# LEF file generated by Abstract Generator version 5.5.10 on Jul 28 14:08:17 2004
#
# Contains LEF for all bins.
# Options:   [x] Antenna
#            [x] Geometry
#            [x] Technology

VERSION 5.4 ;
NAMESCASESENSITIVE ON ;
BUSBITCHARS "[]" ;
DIVIDERCHAR "/" ;
UNITS
  DATABASE MICRONS 1000 ;
END UNITS

USEMINSPACING OBS ON ;
USEMINSPACING PIN OFF ;
CLEARANCEMEASURE EUCLIDEAN ;


MANUFACTURINGGRID 0.075 ;

LAYER nwell
  TYPE	MASTERSLICE ;
END nwell

LAYER nactive
  TYPE	MASTERSLICE ;
END nactive

LAYER pactive
  TYPE	MASTERSLICE ;
END pactive

LAYER poly
  TYPE	MASTERSLICE ;
END poly

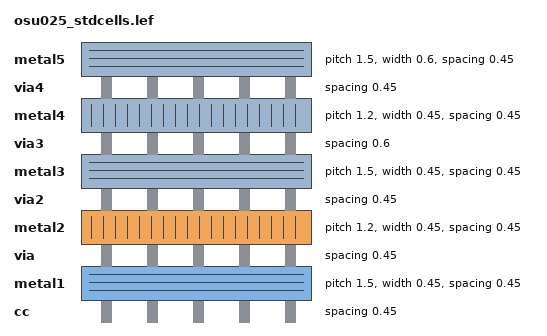
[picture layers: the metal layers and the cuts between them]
LAYER cc
  TYPE	CUT ;
  SPACING	0.45 ;
END cc

LAYER metal1
  TYPE		ROUTING ;
  DIRECTION	HORIZONTAL ;
  PITCH		1.5  ;
  WIDTH		0.45 ;
  SPACING	0.45 ;
  RESISTANCE	RPERSQ 0.07 ;
  CAPACITANCE	CPERSQDIST 3.6e-05 ;
END metal1

LAYER via
  TYPE	CUT ;
  SPACING	0.45 ;
END via

LAYER metal2
  TYPE		ROUTING ;
  DIRECTION	VERTICAL ;
  PITCH		1.2  ;
  WIDTH		0.45 ;
  SPACING	0.45 ;
  RESISTANCE	RPERSQ 0.07 ;
  CAPACITANCE	CPERSQDIST 1.6e-05 ;
END metal2

LAYER via2
  TYPE	CUT ;
  SPACING	0.45 ;
END via2

LAYER metal3
  TYPE		ROUTING ;
  DIRECTION	HORIZONTAL ;
  PITCH		1.5  ;
  WIDTH		0.45 ;
  SPACING	0.45 ;
  RESISTANCE	RPERSQ 0.07 ;
  CAPACITANCE	CPERSQDIST 1e-05 ;
END metal3

LAYER via3
  TYPE	CUT ;
  SPACING	0.6 ;
END via3

LAYER metal4
  TYPE		ROUTING ;
  DIRECTION	VERTICAL ;
  PITCH		1.2  ;
  WIDTH		0.45 ;
  SPACING	0.45 ;
  RESISTANCE	RPERSQ 0.07 ;
  CAPACITANCE	CPERSQDIST 5e-06 ;
END metal4

LAYER via4
  TYPE	CUT ;
  SPACING	0.45 ;
END via4

LAYER metal5
  TYPE		ROUTING ;
  DIRECTION	HORIZONTAL ;
  PITCH		1.5  ;
  WIDTH		0.6 ;
  SPACING	0.45 ;
  RESISTANCE	RPERSQ 0.02 ;
  CAPACITANCE	CPERSQDIST 4e-06 ;
END metal5

VIA M2_M1 DEFAULT
  LAYER metal1 ;
    RECT -0.300 -0.300 0.300 0.300 ;
  LAYER via ;
    RECT -0.150 -0.150 0.150 0.150 ;
  LAYER metal2 ;
    RECT -0.300 -0.300 0.300 0.300 ;
END M2_M1

VIA M3_M2 DEFAULT
  LAYER metal2 ;
    RECT -0.300 -0.300 0.300 0.300 ;
  LAYER via2 ;
    RECT -0.150 -0.150 0.150 0.150 ;
  LAYER metal3 ;
    RECT -0.300 -0.300 0.300 0.300 ;
END M3_M2

VIA M4_M3 DEFAULT
  LAYER metal3 ;
    RECT -0.300 -0.300 0.300 0.300 ;
  LAYER via3 ;
    RECT -0.150 -0.150 0.150 0.150 ;
  LAYER metal4 ;
    RECT -0.300 -0.300 0.300 0.300 ;
END M4_M3

VIA M5_M4 DEFAULT
  LAYER metal4 ;
    RECT -0.300 -0.300 0.300 0.300 ;
  LAYER via4 ;
    RECT -0.150 -0.150 0.150 0.150 ;
  LAYER metal5 ;
    RECT -0.300 -0.300 0.300 0.300 ;
END M5_M4


VIARULE viagen21 GENERATE
  LAYER metal1 ;
    DIRECTION HORIZONTAL ;
    WIDTH 0.6 TO 60 ;
    OVERHANG 0.15 ;
    METALOVERHANG 0 ;
  LAYER metal2 ;
    DIRECTION VERTICAL ;
    WIDTH 0.6 TO 60 ;
    OVERHANG 0.15 ;
    METALOVERHANG 0 ;
  LAYER via ;
    RECT -0.15 -0.15 0.15 0.15 ;
    SPACING 0.75 BY 0.75 ;
END viagen21

VIARULE viagen32 GENERATE
  LAYER metal3 ;
    DIRECTION HORIZONTAL ;
    WIDTH 0.6 TO 60 ;
    OVERHANG 0.15 ;
    METALOVERHANG 0 ;
  LAYER metal2 ;
    DIRECTION VERTICAL ;
    WIDTH 0.6 TO 60 ;
    OVERHANG 0.15 ;
    METALOVERHANG 0 ;
  LAYER via2 ;
    RECT -0.15 -0.15 0.15 0.15 ;
    SPACING 0.75 BY 0.75 ;
END viagen32

VIARULE viagen43 GENERATE
  LAYER metal3 ;
    DIRECTION HORIZONTAL ;
    WIDTH 0.6 TO 60 ;
    OVERHANG 0.15 ;
    METALOVERHANG 0 ;
  LAYER metal4 ;
    DIRECTION VERTICAL ;
    WIDTH 0.6 TO 60 ;
    OVERHANG 0.15 ;
    METALOVERHANG 0 ;
  LAYER via3 ;
    RECT -0.15 -0.15 0.15 0.15 ;
    SPACING 0.9 BY 0.9 ;
END viagen43

VIARULE viagen54 GENERATE
  LAYER metal5 ;
    DIRECTION HORIZONTAL ;
    WIDTH 0.6 TO 60 ;
    OVERHANG 0.15 ;
    METALOVERHANG 0 ;
  LAYER metal4 ;
    DIRECTION VERTICAL ;
    WIDTH 0.6 TO 60 ;
    OVERHANG 0.15 ;
    METALOVERHANG 0 ;
  LAYER via4 ;
    RECT -0.15 -0.15 0.15 0.15 ;
    SPACING 0.75 BY 0.75 ;
END viagen54

VIARULE TURN1 GENERATE
  LAYER metal1 ;
    DIRECTION HORIZONTAL ;
  LAYER metal1 ;
    DIRECTION VERTICAL ;
END TURN1

VIARULE TURN2 GENERATE
  LAYER metal2 ;
    DIRECTION HORIZONTAL ;
  LAYER metal2 ;
    DIRECTION VERTICAL ;
END TURN2

VIARULE TURN3 GENERATE
  LAYER metal3 ;
    DIRECTION HORIZONTAL ;
  LAYER metal3 ;
    DIRECTION VERTICAL ;
END TURN3

VIARULE TURN4 GENERATE
  LAYER metal4 ;
    DIRECTION HORIZONTAL ;
  LAYER metal4 ;
    DIRECTION VERTICAL ;
END TURN4

VIARULE TURN5 GENERATE
  LAYER metal5 ;
    DIRECTION HORIZONTAL ;
  LAYER metal5 ;
    DIRECTION VERTICAL ;
END TURN5

SITE  core
    CLASS	CORE ;
    SYMMETRY	Y ;
    SIZE	1.200 BY 15.000 ;
END  core

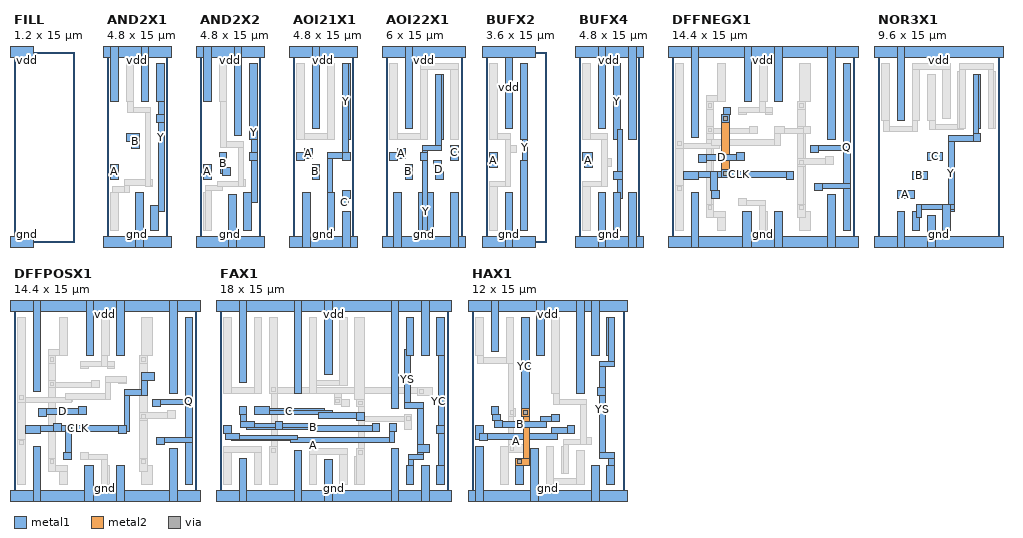
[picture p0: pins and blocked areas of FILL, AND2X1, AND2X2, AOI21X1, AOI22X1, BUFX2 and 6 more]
MACRO FILL
  CLASS  CORE ;
  FOREIGN FILL 0.000 0.000 ;
  ORIGIN 0.000 0.000 ;
  SIZE 1.200 BY 15.000 ;
  SYMMETRY X Y  ;
  SITE core ;
  PIN gnd
    DIRECTION INOUT ;
    USE GROUND ;
    SHAPE ABUTMENT ;
    PORT
      LAYER metal1 ;
        RECT -0.300 -0.450 1.500 0.450 ;
    END
  END gnd
  PIN vdd
    DIRECTION INOUT ;
    USE POWER ;
    SHAPE ABUTMENT ;
    PORT
      LAYER metal1 ;
        RECT -0.300 14.550 1.500 15.450 ;
    END
  END vdd
END FILL

MACRO AND2X1
  CLASS  CORE ;
  FOREIGN AND2X1 0.000 0.000 ;
  ORIGIN 0.000 0.000 ;
  SIZE 4.800 BY 15.000 ;
  SYMMETRY X Y  ;
  SITE core ;
  PIN A
    DIRECTION INPUT ;
    PORT
      LAYER metal1 ;
        RECT 0.300 4.950 0.900 6.150 ;
    END
  END A
  PIN B
    DIRECTION INPUT ;
    PORT
      LAYER metal1 ;
        RECT 1.950 7.350 2.550 8.550 ;
        RECT 1.500 7.950 2.550 8.550 ;
    END
  END B
  PIN gnd
    DIRECTION INOUT ;
    USE GROUND ;
    SHAPE ABUTMENT ;
    PORT
      LAYER metal1 ;
        RECT 2.250 -0.450 2.850 3.900 ;
        RECT -0.300 -0.450 5.100 0.450 ;
    END
  END gnd
  PIN Y
    DIRECTION OUTPUT ;
    PORT
      LAYER metal1 ;
        RECT 3.900 9.450 4.500 10.050 ;
        RECT 3.900 11.100 4.500 14.100 ;
        RECT 4.050 2.400 4.500 14.100 ;
        RECT 3.450 0.900 4.050 2.850 ;
    END
  END Y
  PIN vdd
    DIRECTION INOUT ;
    USE POWER ;
    SHAPE ABUTMENT ;
    PORT
      LAYER metal1 ;
        RECT 0.300 11.100 0.900 15.450 ;
        RECT -0.300 14.550 5.100 15.450 ;
        RECT 2.700 11.100 3.300 15.450 ;
    END
  END vdd
  OBS 
      LAYER metal1 ;
        RECT 0.300 0.900 0.900 3.900 ;
        RECT 0.450 3.900 1.800 4.350 ;
        RECT 1.350 3.900 1.800 4.950 ;
        RECT 3.000 4.350 3.600 4.950 ;
        RECT 1.350 4.500 3.600 4.950 ;
        RECT 3.000 4.350 3.450 10.650 ;
        RECT 1.650 10.200 3.450 10.650 ;
        RECT 1.650 10.200 2.100 14.100 ;
        RECT 1.500 11.100 2.100 14.100 ;
  END 
END AND2X1

MACRO AND2X2
  CLASS  CORE ;
  FOREIGN AND2X2 0.000 0.000 ;
  ORIGIN 0.000 0.000 ;
  SIZE 4.800 BY 15.000 ;
  SYMMETRY X Y  ;
  SITE core ;
  PIN A
    DIRECTION INPUT ;
    PORT
      LAYER metal1 ;
        RECT 0.300 4.950 0.900 6.150 ;
    END
  END A
  PIN B
    DIRECTION INPUT ;
    PORT
      LAYER metal1 ;
        RECT 1.650 5.400 2.100 7.050 ;
        RECT 1.800 5.250 2.400 5.850 ;
        RECT 1.500 6.450 2.100 7.050 ;
    END
  END B
  PIN gnd
    DIRECTION INOUT ;
    USE GROUND ;
    SHAPE ABUTMENT ;
    PORT
      LAYER metal1 ;
        RECT 2.250 -0.450 2.850 3.750 ;
        RECT -0.300 -0.450 5.100 0.450 ;
    END
  END gnd
  PIN Y
    DIRECTION OUTPUT ;
    PORT
      LAYER metal1 ;
        RECT 3.900 6.450 4.500 7.050 ;
        RECT 3.900 8.100 4.500 14.100 ;
        RECT 4.050 3.150 4.500 14.100 ;
        RECT 3.450 0.900 4.050 3.900 ;
    END
  END Y
  PIN vdd
    DIRECTION INOUT ;
    USE POWER ;
    SHAPE ABUTMENT ;
    PORT
      LAYER metal1 ;
        RECT 0.300 11.100 0.900 15.450 ;
        RECT -0.300 14.550 5.100 15.450 ;
        RECT 2.700 8.400 3.300 15.450 ;
    END
  END vdd
  OBS 
      LAYER metal1 ;
        RECT 0.300 0.900 0.900 3.900 ;
        RECT 0.450 0.900 0.900 4.500 ;
        RECT 0.450 4.050 1.800 4.500 ;
        RECT 1.350 4.350 3.600 4.800 ;
        RECT 3.000 4.350 3.600 4.950 ;
        RECT 3.000 4.350 3.450 7.950 ;
        RECT 1.650 7.500 3.450 7.950 ;
        RECT 1.650 7.500 2.100 14.100 ;
        RECT 1.500 11.100 2.100 14.100 ;
  END 
END AND2X2

MACRO AOI21X1
  CLASS  CORE ;
  FOREIGN AOI21X1 0.000 0.000 ;
  ORIGIN 0.000 0.000 ;
  SIZE 4.800 BY 15.000 ;
  SYMMETRY X Y  ;
  SITE core ;
  PIN A
    DIRECTION INPUT ;
    PORT
      LAYER metal1 ;
        RECT 0.300 6.450 0.900 7.050 ;
        RECT 0.900 6.600 1.500 7.350 ;
    END
  END A
  PIN B
    DIRECTION INPUT ;
    PORT
      LAYER metal1 ;
        RECT 1.500 4.950 2.100 6.150 ;
    END
  END B
  PIN C
    DIRECTION INPUT ;
    PORT
      LAYER metal1 ;
        RECT 3.750 2.850 4.350 3.450 ;
        RECT 3.900 3.450 4.500 4.050 ;
    END
  END C
  PIN gnd
    DIRECTION INOUT ;
    USE GROUND ;
    SHAPE ABUTMENT ;
    PORT
      LAYER metal1 ;
        RECT 0.750 -0.450 1.350 3.900 ;
        RECT -0.300 -0.450 5.100 0.450 ;
        RECT 3.900 -0.450 4.500 2.400 ;
    END
  END gnd
  PIN Y
    DIRECTION OUTPUT ;
    PORT
      LAYER metal1 ;
        RECT 2.700 0.900 3.150 7.050 ;
        RECT 3.900 8.100 4.500 14.100 ;
        RECT 2.700 6.600 4.500 7.050 ;
        RECT 3.900 6.450 4.500 7.050 ;
        RECT 3.900 6.450 4.350 14.100 ;
        RECT 2.700 0.900 3.300 3.900 ;
    END
  END Y
  PIN vdd
    DIRECTION INOUT ;
    USE POWER ;
    SHAPE ABUTMENT ;
    PORT
      LAYER metal1 ;
        RECT 1.500 9.000 2.100 15.450 ;
        RECT -0.300 14.550 5.100 15.450 ;
    END
  END vdd
  OBS 
      LAYER metal1 ;
        RECT 0.300 8.100 3.300 8.550 ;
        RECT 0.300 8.100 0.900 14.100 ;
        RECT 2.700 8.100 3.300 14.100 ;
  END 
END AOI21X1

MACRO AOI22X1
  CLASS  CORE ;
  FOREIGN AOI22X1 0.000 0.000 ;
  ORIGIN 0.000 0.000 ;
  SIZE 6.000 BY 15.000 ;
  SYMMETRY X Y  ;
  SITE core ;
  PIN A
    DIRECTION INPUT ;
    PORT
      LAYER metal1 ;
        RECT 0.300 6.450 0.900 7.050 ;
        RECT 0.900 6.600 1.500 7.350 ;
    END
  END A
  PIN B
    DIRECTION INPUT ;
    PORT
      LAYER metal1 ;
        RECT 1.500 4.950 2.100 6.150 ;
    END
  END B
  PIN C
    DIRECTION INPUT ;
    PORT
      LAYER metal1 ;
        RECT 5.100 6.450 5.700 7.650 ;
    END
  END C
  PIN D
    DIRECTION INPUT ;
    PORT
      LAYER metal1 ;
        RECT 3.900 4.950 4.350 6.450 ;
        RECT 3.900 4.950 4.500 5.550 ;
        RECT 3.750 5.850 4.350 6.450 ;
    END
  END D
  PIN gnd
    DIRECTION INOUT ;
    USE GROUND ;
    SHAPE ABUTMENT ;
    PORT
      LAYER metal1 ;
        RECT 0.600 -0.450 1.200 3.900 ;
        RECT -0.300 -0.450 6.300 0.450 ;
        RECT 5.100 -0.450 5.700 3.900 ;
    END
  END gnd
  PIN Y
    DIRECTION OUTPUT ;
    PORT
      LAYER metal1 ;
        RECT 2.700 6.450 3.300 7.050 ;
        RECT 3.900 8.100 4.500 13.200 ;
        RECT 3.900 7.200 4.350 13.200 ;
        RECT 2.850 7.200 4.350 7.650 ;
        RECT 2.550 0.900 3.750 3.900 ;
        RECT 2.850 0.900 3.300 7.650 ;
    END
  END Y
  PIN vdd
    DIRECTION INOUT ;
    USE POWER ;
    SHAPE ABUTMENT ;
    PORT
      LAYER metal1 ;
        RECT 1.500 9.000 2.100 15.450 ;
        RECT -0.300 14.550 6.300 15.450 ;
    END
  END vdd
  OBS 
      LAYER metal1 ;
        RECT 0.300 8.100 3.300 8.550 ;
        RECT 2.700 8.100 3.300 14.100 ;
        RECT 0.300 8.100 0.900 14.100 ;
        RECT 5.100 8.100 5.700 14.100 ;
        RECT 2.700 13.650 5.700 14.100 ;
  END 
END AOI22X1

MACRO BUFX2
  CLASS  CORE ;
  FOREIGN BUFX2 0.000 0.000 ;
  ORIGIN 0.000 0.000 ;
  SIZE 3.600 BY 15.000 ;
  SYMMETRY X Y  ;
  SITE core ;
  PIN A
    DIRECTION INPUT ;
    PORT
      LAYER metal1 ;
        RECT 0.300 5.850 0.900 7.050 ;
    END
  END A
  PIN gnd
    DIRECTION INOUT ;
    USE GROUND ;
    SHAPE ABUTMENT ;
    PORT
      LAYER metal1 ;
        RECT 1.500 -0.450 2.100 3.900 ;
        RECT -0.300 -0.450 3.900 0.450 ;
    END
  END gnd
  PIN Y
    DIRECTION OUTPUT ;
    PORT
      LAYER metal1 ;
        RECT 2.700 0.900 3.300 6.450 ;
        RECT 2.700 8.100 3.300 14.100 ;
        RECT 2.850 0.900 3.300 14.100 ;
    END
  END Y
  PIN vdd
    DIRECTION INOUT ;
    USE POWER ;
    SHAPE ABUTMENT ;
    PORT
      LAYER metal1 ;
        RECT 1.500 9.000 2.100 15.450 ;
        RECT -0.300 14.550 3.900 15.450 ;
    END
  END vdd
  OBS 
      LAYER metal1 ;
        RECT 0.300 0.900 0.900 4.800 ;
        RECT 0.300 4.350 1.950 4.800 ;
        RECT 1.500 7.050 2.400 7.650 ;
        RECT 1.500 4.350 1.950 8.550 ;
        RECT 0.300 8.100 1.950 8.550 ;
        RECT 0.300 8.100 0.900 14.100 ;
  END 
END BUFX2

MACRO BUFX4
  CLASS  CORE ;
  FOREIGN BUFX4 0.000 0.000 ;
  ORIGIN 0.000 0.000 ;
  SIZE 4.800 BY 15.000 ;
  SYMMETRY X Y  ;
  SITE core ;
  PIN A
    DIRECTION INPUT ;
    PORT
      LAYER metal1 ;
        RECT 0.450 5.850 1.050 7.050 ;
        RECT 0.300 6.450 1.050 7.050 ;
    END
  END A
  PIN gnd
    DIRECTION INOUT ;
    USE GROUND ;
    SHAPE ABUTMENT ;
    PORT
      LAYER metal1 ;
        RECT 1.500 -0.450 2.100 3.900 ;
        RECT -0.300 -0.450 5.100 0.450 ;
        RECT 3.900 -0.450 4.500 3.900 ;
    END
  END gnd
  PIN Y
    DIRECTION OUTPUT ;
    PORT
      LAYER metal1 ;
        RECT 2.700 0.900 3.300 3.900 ;
        RECT 3.000 3.450 3.450 8.850 ;
        RECT 2.700 8.100 3.300 14.100 ;
        RECT 2.700 4.950 3.450 5.550 ;
    END
  END Y
  PIN vdd
    DIRECTION INOUT ;
    USE POWER ;
    SHAPE ABUTMENT ;
    PORT
      LAYER metal1 ;
        RECT 1.500 9.000 2.100 15.450 ;
        RECT -0.300 14.550 5.100 15.450 ;
        RECT 3.900 8.100 4.500 15.450 ;
    END
  END vdd
  OBS 
      LAYER metal1 ;
        RECT 0.300 0.900 0.900 4.800 ;
        RECT 0.300 4.350 2.250 4.800 ;
        RECT 1.800 6.000 2.550 6.600 ;
        RECT 1.800 4.350 2.250 8.550 ;
        RECT 0.300 8.100 2.250 8.550 ;
        RECT 0.300 8.100 0.900 14.100 ;
  END 
END BUFX4

MACRO DFFNEGX1
  CLASS  CORE ;
  FOREIGN DFFNEGX1 0.000 0.000 ;
  ORIGIN 0.000 0.000 ;
  SIZE 14.400 BY 15.000 ;
  SYMMETRY X Y  ;
  SITE core ;
  PIN Q
    DIRECTION OUTPUT ;
    PORT
      LAYER metal1 ;
        RECT 10.950 7.050 11.550 7.650 ;
        RECT 13.500 0.900 14.100 14.100 ;
        RECT 10.950 7.200 14.100 7.650 ;
        RECT 11.250 4.200 14.100 4.650 ;
        RECT 11.250 4.050 11.850 4.650 ;
    END
  END Q
  PIN CLK
    DIRECTION INPUT ;
    USE CLOCK ;
    PORT
      LAYER metal2 ;
        RECT 3.900 5.100 4.500 10.050 ;
      LAYER via ;
        RECT 4.050 9.600 4.350 9.900 ;
        RECT 4.050 5.250 4.350 5.550 ;
      LAYER metal1 ;
        RECT 3.900 9.450 4.500 10.050 ;
        RECT 0.900 5.100 9.600 5.550 ;
        RECT 9.000 4.950 9.600 5.550 ;
        RECT 3.900 5.100 4.500 5.700 ;
        RECT 3.150 3.450 3.750 4.050 ;
        RECT 3.000 4.050 3.600 5.550 ;
        RECT 0.900 4.950 2.100 5.550 ;
        RECT 4.050 10.050 4.650 10.650 ;
    END
  END CLK
  PIN D
    DIRECTION INPUT ;
    PORT
      LAYER metal1 ;
        RECT 2.100 6.300 2.700 6.900 ;
        RECT 5.100 6.450 5.700 7.050 ;
        RECT 2.100 6.450 5.700 6.900 ;
    END
  END D
  PIN gnd
    DIRECTION INOUT ;
    USE GROUND ;
    SHAPE ABUTMENT ;
    PORT
      LAYER metal1 ;
        RECT 1.500 -0.450 2.100 3.900 ;
        RECT -0.300 -0.450 14.700 0.450 ;
        RECT 12.300 -0.450 12.900 3.750 ;
        RECT 8.100 -0.450 8.700 2.400 ;
        RECT 5.550 -0.450 6.300 2.400 ;
    END
  END gnd
  PIN vdd
    DIRECTION INOUT ;
    USE POWER ;
    SHAPE ABUTMENT ;
    PORT
      LAYER metal1 ;
        RECT 1.500 8.250 2.100 15.450 ;
        RECT -0.300 14.550 14.700 15.450 ;
        RECT 12.300 8.100 12.900 15.450 ;
        RECT 8.100 11.100 8.700 15.450 ;
        RECT 5.700 11.100 6.300 15.450 ;
    END
  END vdd
  OBS 
      LAYER metal2 ;
        RECT 0.300 3.900 0.900 8.100 ;
        RECT 2.700 2.400 3.300 7.500 ;
        RECT 2.700 2.400 3.150 11.100 ;
        RECT 2.700 8.100 3.300 11.100 ;
        RECT 9.900 2.400 10.500 8.550 ;
        RECT 9.900 2.400 10.350 11.100 ;
        RECT 9.900 9.150 10.500 11.100 ;
      LAYER metal1 ;
        RECT 0.300 0.900 0.900 4.500 ;
        RECT 2.700 10.500 3.300 11.550 ;
        RECT 2.700 11.100 4.200 11.550 ;
        RECT 3.600 11.100 4.200 14.100 ;
        RECT 3.600 0.900 4.200 2.400 ;
        RECT 2.700 1.950 4.200 2.400 ;
        RECT 2.700 1.950 3.300 3.000 ;
        RECT 2.700 8.550 6.750 9.000 ;
        RECT 2.700 8.550 3.300 9.150 ;
        RECT 6.150 8.550 6.750 9.150 ;
        RECT 6.900 0.900 7.500 2.400 ;
        RECT 6.900 0.900 7.350 3.300 ;
        RECT 5.250 2.850 7.350 3.300 ;
        RECT 5.250 2.850 5.850 3.450 ;
        RECT 5.250 10.050 5.850 10.650 ;
        RECT 7.350 10.050 7.950 10.650 ;
        RECT 5.250 10.200 7.950 10.650 ;
        RECT 6.900 10.200 7.350 14.100 ;
        RECT 6.900 11.100 7.500 14.100 ;
        RECT 9.900 10.500 10.500 11.100 ;
        RECT 10.050 11.100 10.950 14.100 ;
        RECT 0.300 7.350 3.750 7.800 ;
        RECT 3.150 7.650 8.550 8.100 ;
        RECT 8.100 7.650 8.550 9.150 ;
        RECT 8.100 8.550 10.950 9.000 ;
        RECT 8.100 8.550 8.850 9.150 ;
        RECT 10.350 8.550 10.950 9.150 ;
        RECT 0.300 7.350 0.900 14.100 ;
        RECT 10.050 0.900 10.950 2.400 ;
        RECT 9.900 1.950 10.500 3.000 ;
        RECT 9.900 6.000 10.500 6.600 ;
        RECT 9.900 6.150 12.750 6.600 ;
        RECT 12.150 6.150 12.750 6.750 ;
      LAYER via ;
        RECT 0.450 7.650 0.750 7.950 ;
        RECT 0.450 4.050 0.750 4.350 ;
        RECT 2.850 10.650 3.150 10.950 ;
        RECT 2.850 8.700 3.150 9.000 ;
        RECT 2.850 2.550 3.150 2.850 ;
        RECT 10.050 10.650 10.350 10.950 ;
        RECT 10.050 6.150 10.350 6.450 ;
        RECT 10.050 2.550 10.350 2.850 ;
  END 
END DFFNEGX1

MACRO NOR3X1
  CLASS  CORE ;
  FOREIGN NOR3X1 0.000 0.000 ;
  ORIGIN 0.000 0.000 ;
  SIZE 9.600 BY 15.000 ;
  SYMMETRY X Y  ;
  SITE core ;
  PIN A
    DIRECTION INPUT ;
    PORT
      LAYER metal1 ;
        RECT 1.500 3.450 2.850 4.050 ;
    END
  END A
  PIN B
    DIRECTION INPUT ;
    PORT
      LAYER metal1 ;
        RECT 2.700 4.950 3.900 5.550 ;
    END
  END B
  PIN C
    DIRECTION INPUT ;
    PORT
      LAYER metal1 ;
        RECT 3.900 6.450 5.100 7.050 ;
    END
  END C
  PIN gnd
    DIRECTION INOUT ;
    USE GROUND ;
    SHAPE ABUTMENT ;
    PORT
      LAYER metal1 ;
        RECT 1.500 -0.450 2.100 2.400 ;
        RECT -0.300 -0.450 9.900 0.450 ;
        RECT 3.900 -0.450 4.500 2.100 ;
    END
  END gnd
  PIN Y
    DIRECTION OUTPUT ;
    PORT
      LAYER metal1 ;
        RECT 2.700 0.900 3.300 2.400 ;
        RECT 7.500 9.000 8.100 13.200 ;
        RECT 7.500 7.950 8.100 8.550 ;
        RECT 7.500 7.950 7.950 13.200 ;
        RECT 5.550 7.950 8.100 8.400 ;
        RECT 5.550 2.400 6.000 8.400 ;
        RECT 5.100 0.900 5.700 3.000 ;
        RECT 3.000 2.550 6.000 3.000 ;
        RECT 3.000 1.950 3.450 3.000 ;
    END
  END Y
  PIN vdd
    DIRECTION INOUT ;
    USE POWER ;
    SHAPE ABUTMENT ;
    PORT
      LAYER metal1 ;
        RECT 1.500 9.600 2.100 15.450 ;
        RECT -0.300 14.550 9.900 15.450 ;
    END
  END vdd
  OBS 
      LAYER metal1 ;
        RECT 0.450 8.700 3.150 9.150 ;
        RECT 2.700 8.700 3.150 14.100 ;
        RECT 2.700 9.600 3.300 14.100 ;
        RECT 0.450 8.700 0.900 14.100 ;
        RECT 0.300 9.600 0.900 14.100 ;
        RECT 5.100 9.750 5.700 14.100 ;
        RECT 2.700 13.650 5.700 14.100 ;
        RECT 4.050 8.850 6.750 9.300 ;
        RECT 4.050 8.850 4.500 13.200 ;
        RECT 3.900 9.600 4.500 13.200 ;
        RECT 6.300 9.000 6.900 13.500 ;
        RECT 8.700 9.000 9.300 13.500 ;
        RECT 6.450 9.000 6.900 14.100 ;
        RECT 8.700 9.000 9.150 14.100 ;
        RECT 6.450 13.650 9.150 14.100 ;
  END 
END NOR3X1

MACRO DFFPOSX1
  CLASS  CORE ;
  FOREIGN DFFPOSX1 0.000 0.000 ;
  ORIGIN 0.000 0.000 ;
  SIZE 14.400 BY 15.000 ;
  SYMMETRY X Y  ;
  SITE core ;
  PIN Q
    DIRECTION OUTPUT ;
    PORT
      LAYER metal1 ;
        RECT 10.950 7.050 11.550 7.650 ;
        RECT 13.500 0.900 14.100 14.100 ;
        RECT 10.950 7.200 14.100 7.650 ;
        RECT 11.250 4.200 14.100 4.650 ;
        RECT 11.250 4.050 11.850 4.650 ;
    END
  END Q
  PIN CLK
    DIRECTION INPUT ;
    USE CLOCK ;
    PORT
      LAYER metal1 ;
        RECT 0.900 4.950 2.100 5.550 ;
        RECT 10.050 9.150 11.100 9.750 ;
        RECT 10.050 7.950 10.500 9.750 ;
        RECT 8.700 7.950 10.500 8.400 ;
        RECT 8.700 5.100 9.150 8.400 ;
        RECT 8.250 4.950 8.850 5.550 ;
        RECT 0.900 5.100 9.150 5.550 ;
        RECT 4.050 2.850 4.500 5.550 ;
        RECT 3.900 2.850 4.500 3.450 ;
        RECT 3.150 5.100 3.750 5.700 ;
    END
  END CLK
  PIN D
    DIRECTION INPUT ;
    PORT
      LAYER metal1 ;
        RECT 1.950 6.300 2.550 6.900 ;
        RECT 5.100 6.450 5.700 7.050 ;
        RECT 1.950 6.450 5.700 6.900 ;
    END
  END D
  PIN gnd
    DIRECTION INOUT ;
    USE GROUND ;
    SHAPE ABUTMENT ;
    PORT
      LAYER metal1 ;
        RECT 1.500 -0.450 2.100 3.900 ;
        RECT -0.300 -0.450 14.700 0.450 ;
        RECT 12.300 -0.450 12.900 3.750 ;
        RECT 8.100 -0.450 8.700 2.400 ;
        RECT 5.550 -0.450 6.300 2.400 ;
    END
  END gnd
  PIN vdd
    DIRECTION INOUT ;
    USE POWER ;
    SHAPE ABUTMENT ;
    PORT
      LAYER metal1 ;
        RECT 1.500 8.250 2.100 15.450 ;
        RECT -0.300 14.550 14.700 15.450 ;
        RECT 12.300 8.100 12.900 15.450 ;
        RECT 8.100 11.100 8.700 15.450 ;
        RECT 5.700 11.100 6.300 15.450 ;
    END
  END vdd
  OBS 
      LAYER metal2 ;
        RECT 0.300 3.900 0.900 8.100 ;
        RECT 2.700 2.400 3.300 11.100 ;
        RECT 9.900 2.400 10.500 11.100 ;
      LAYER metal1 ;
        RECT 0.300 0.900 0.900 4.500 ;
        RECT 2.700 10.500 3.300 11.550 ;
        RECT 2.700 11.100 4.200 11.550 ;
        RECT 3.600 11.100 4.200 14.100 ;
        RECT 3.600 0.900 4.200 2.400 ;
        RECT 2.700 1.950 4.200 2.400 ;
        RECT 2.700 1.950 3.300 3.000 ;
        RECT 2.700 8.550 6.750 9.000 ;
        RECT 2.700 8.550 3.300 9.150 ;
        RECT 6.150 8.550 6.750 9.150 ;
        RECT 6.900 0.900 7.500 2.400 ;
        RECT 6.900 0.900 7.350 3.300 ;
        RECT 5.250 2.850 7.350 3.300 ;
        RECT 5.250 2.850 5.850 3.450 ;
        RECT 5.250 10.050 5.850 10.650 ;
        RECT 7.350 10.050 7.950 10.650 ;
        RECT 5.250 10.200 7.950 10.650 ;
        RECT 6.900 10.200 7.350 14.100 ;
        RECT 6.900 11.100 7.500 14.100 ;
        RECT 0.300 7.500 4.650 7.800 ;
        RECT 0.300 7.350 4.500 7.800 ;
        RECT 4.050 7.650 7.650 8.100 ;
        RECT 7.200 7.650 7.650 9.450 ;
        RECT 8.250 8.850 8.850 9.450 ;
        RECT 7.200 9.000 8.850 9.450 ;
        RECT 0.300 7.350 0.900 14.100 ;
        RECT 9.900 10.500 10.500 11.100 ;
        RECT 10.050 11.100 10.950 14.100 ;
        RECT 10.050 0.900 10.950 2.400 ;
        RECT 9.900 1.950 10.500 3.000 ;
        RECT 9.900 6.000 10.500 6.600 ;
        RECT 9.900 6.150 12.750 6.600 ;
        RECT 12.150 6.150 12.750 6.750 ;
      LAYER via ;
        RECT 0.450 7.650 0.750 7.950 ;
        RECT 0.450 4.050 0.750 4.350 ;
        RECT 2.850 10.650 3.150 10.950 ;
        RECT 2.850 8.700 3.150 9.000 ;
        RECT 2.850 2.550 3.150 2.850 ;
        RECT 10.050 10.650 10.350 10.950 ;
        RECT 10.050 6.150 10.350 6.450 ;
        RECT 10.050 2.550 10.350 2.850 ;
  END 
END DFFPOSX1

MACRO FAX1
  CLASS  CORE ;
  FOREIGN FAX1 0.000 0.000 ;
  ORIGIN 0.000 0.000 ;
  SIZE 18.000 BY 15.000 ;
  SYMMETRY X Y  ;
  SITE core ;
  PIN YC
    DIRECTION OUTPUT ;
    PORT
      LAYER metal1 ;
        RECT 17.100 0.900 17.700 2.400 ;
        RECT 17.100 11.100 17.700 14.100 ;
        RECT 17.250 0.900 17.700 14.100 ;
        RECT 17.100 4.950 17.700 5.550 ;
    END
  END YC
  PIN YS
    DIRECTION OUTPUT ;
    PORT
      LAYER metal1 ;
        RECT 14.700 0.900 15.300 2.400 ;
        RECT 15.600 3.450 16.500 4.050 ;
        RECT 14.550 6.900 16.050 7.350 ;
        RECT 15.600 2.850 16.050 7.350 ;
        RECT 14.850 2.850 16.050 3.300 ;
        RECT 14.700 11.100 15.300 14.100 ;
        RECT 14.850 0.900 15.300 3.300 ;
        RECT 14.550 6.900 15.000 11.550 ;
    END
  END YS
  PIN A
    DIRECTION INPUT ;
    PORT
      LAYER metal1 ;
        RECT 0.450 4.500 1.500 4.950 ;
        RECT 13.350 5.100 13.950 5.700 ;
        RECT 13.350 4.200 13.800 5.700 ;
        RECT 5.550 4.200 13.800 4.650 ;
        RECT 0.450 4.500 6.150 4.800 ;
        RECT 0.900 4.350 13.800 4.650 ;
        RECT 0.300 4.950 0.900 5.550 ;
    END
  END A
  PIN B
    DIRECTION INPUT ;
    PORT
      LAYER metal1 ;
        RECT 1.650 5.400 2.100 7.050 ;
        RECT 12.000 5.100 12.600 5.700 ;
        RECT 7.050 5.100 12.600 5.550 ;
        RECT 1.650 5.400 7.650 5.700 ;
        RECT 2.100 5.250 12.600 5.550 ;
        RECT 4.350 5.250 4.950 5.850 ;
        RECT 1.650 5.400 2.700 5.850 ;
        RECT 1.500 6.450 2.100 7.050 ;
    END
  END B
  PIN C
    DIRECTION INPUT ;
    PORT
      LAYER metal1 ;
        RECT 2.700 6.450 3.900 7.050 ;
        RECT 10.800 6.000 11.400 6.600 ;
        RECT 7.800 6.150 11.400 6.600 ;
        RECT 2.700 6.450 8.850 6.750 ;
        RECT 2.700 6.450 8.250 6.900 ;
    END
  END C
  PIN gnd
    DIRECTION INOUT ;
    USE GROUND ;
    SHAPE ABUTMENT ;
    PORT
      LAYER metal1 ;
        RECT 1.500 -0.450 2.100 3.000 ;
        RECT -0.300 -0.450 18.300 0.450 ;
        RECT 15.900 -0.450 16.500 2.400 ;
        RECT 13.500 -0.450 14.100 3.750 ;
        RECT 8.250 -0.450 8.850 2.850 ;
        RECT 5.850 -0.450 6.450 3.600 ;
    END
  END gnd
  PIN vdd
    DIRECTION INOUT ;
    USE POWER ;
    SHAPE ABUTMENT ;
    PORT
      LAYER metal1 ;
        RECT 1.500 9.000 2.100 15.450 ;
        RECT -0.300 14.550 18.300 15.450 ;
        RECT 15.900 11.100 16.500 15.450 ;
        RECT 13.500 6.900 14.100 15.450 ;
        RECT 8.250 9.600 8.850 15.450 ;
        RECT 5.850 8.100 6.450 15.450 ;
    END
  END vdd
  OBS 
      LAYER metal2 ;
        RECT 10.800 3.150 11.400 3.750 ;
        RECT 10.950 5.850 15.150 6.300 ;
        RECT 14.550 5.850 15.150 6.450 ;
        RECT 10.950 3.150 11.400 7.650 ;
        RECT 10.800 7.050 11.400 7.650 ;
        RECT 3.900 3.300 4.500 3.900 ;
        RECT 9.000 7.200 9.600 8.550 ;
        RECT 15.600 7.950 16.200 8.550 ;
        RECT 3.900 8.100 16.200 8.550 ;
        RECT 4.050 3.300 4.500 8.700 ;
        RECT 3.900 8.100 4.500 8.700 ;
      LAYER metal1 ;
        RECT 0.300 8.100 3.300 8.550 ;
        RECT 0.300 8.100 0.900 14.100 ;
        RECT 2.700 8.100 3.300 14.100 ;
        RECT 0.300 0.900 0.900 3.900 ;
        RECT 2.700 0.900 3.300 3.900 ;
        RECT 0.300 3.450 3.300 3.900 ;
        RECT 3.900 8.100 4.500 14.100 ;
        RECT 3.900 0.900 4.500 3.900 ;
        RECT 7.050 8.700 10.050 9.150 ;
        RECT 7.050 8.100 7.650 14.100 ;
        RECT 9.450 8.700 10.050 14.100 ;
        RECT 7.050 0.900 7.650 3.750 ;
        RECT 9.450 0.900 10.050 3.750 ;
        RECT 7.050 3.300 10.050 3.750 ;
        RECT 9.600 7.050 10.200 7.650 ;
        RECT 9.000 7.200 9.600 7.800 ;
        RECT 10.800 7.050 11.400 14.100 ;
        RECT 10.650 7.650 11.400 14.100 ;
        RECT 10.650 0.900 11.400 3.150 ;
        RECT 10.800 0.900 11.400 3.750 ;
        RECT 14.550 5.250 15.150 6.450 ;
        RECT 15.600 7.950 16.800 8.550 ;
      LAYER via ;
        RECT 4.050 8.250 4.350 8.550 ;
        RECT 4.050 3.450 4.350 3.750 ;
        RECT 9.150 7.350 9.450 7.650 ;
        RECT 10.950 7.200 11.250 7.500 ;
        RECT 10.950 3.300 11.250 3.600 ;
        RECT 14.700 6.000 15.000 6.300 ;
        RECT 15.750 8.100 16.050 8.400 ;
  END 
END FAX1

MACRO HAX1
  CLASS  CORE ;
  FOREIGN HAX1 0.000 0.000 ;
  ORIGIN 0.000 0.000 ;
  SIZE 12.000 BY 15.000 ;
  SYMMETRY X Y  ;
  SITE core ;
  PIN YC
    DIRECTION OUTPUT ;
    PORT
      LAYER metal2 ;
        RECT 3.450 2.400 4.500 3.000 ;
        RECT 3.900 6.300 4.500 6.900 ;
        RECT 4.050 2.400 4.500 6.900 ;
      LAYER via ;
        RECT 3.600 2.550 3.900 2.850 ;
        RECT 4.050 6.450 4.350 6.750 ;
      LAYER metal1 ;
        RECT 3.450 0.900 4.050 3.000 ;
        RECT 3.900 6.300 4.500 14.100 ;
    END
  END YC
  PIN YS
    DIRECTION OUTPUT ;
    PORT
      LAYER metal1 ;
        RECT 9.900 7.950 10.500 8.550 ;
        RECT 10.650 11.100 11.250 14.100 ;
        RECT 10.800 10.200 11.250 14.100 ;
        RECT 10.050 3.000 11.250 3.450 ;
        RECT 10.800 0.900 11.250 3.450 ;
        RECT 10.050 10.200 11.250 10.650 ;
        RECT 10.650 0.900 11.250 2.400 ;
        RECT 10.050 3.000 10.500 10.650 ;
    END
  END YS
  PIN A
    DIRECTION INPUT ;
    PORT
      LAYER metal1 ;
        RECT 0.300 4.500 0.900 5.550 ;
        RECT 7.500 4.950 8.100 5.550 ;
        RECT 6.300 4.950 8.100 5.400 ;
        RECT 0.300 4.500 6.750 4.950 ;
        RECT 0.600 4.350 1.200 4.950 ;
    END
  END A
  PIN B
    DIRECTION INPUT ;
    PORT
      LAYER metal1 ;
        RECT 1.650 6.000 2.250 6.450 ;
        RECT 6.300 5.850 6.900 6.450 ;
        RECT 5.400 5.850 6.900 6.300 ;
        RECT 1.800 5.400 5.850 5.850 ;
        RECT 1.800 5.400 2.400 6.000 ;
        RECT 1.500 6.450 2.100 7.050 ;
    END
  END B
  PIN gnd
    DIRECTION INOUT ;
    USE GROUND ;
    SHAPE ABUTMENT ;
    PORT
      LAYER metal1 ;
        RECT 0.300 -0.450 0.900 3.900 ;
        RECT -0.300 -0.450 12.300 0.450 ;
        RECT 9.450 -0.450 10.050 2.400 ;
        RECT 4.650 -0.450 5.250 3.750 ;
    END
  END gnd
  PIN vdd
    DIRECTION INOUT ;
    USE POWER ;
    SHAPE ABUTMENT ;
    PORT
      LAYER metal1 ;
        RECT 1.500 11.400 2.100 15.450 ;
        RECT -0.300 14.550 12.300 15.450 ;
        RECT 9.450 11.100 10.050 15.450 ;
        RECT 8.250 8.100 8.850 15.450 ;
        RECT 5.100 11.100 5.700 15.450 ;
    END
  END vdd
  OBS 
      LAYER metal2 ;
        RECT 2.850 3.450 3.450 4.050 ;
        RECT 2.850 3.450 3.300 6.900 ;
        RECT 2.850 6.300 3.450 6.900 ;
      LAYER metal1 ;
        RECT 2.850 6.300 3.450 6.900 ;
        RECT 0.450 10.500 3.300 10.950 ;
        RECT 0.450 10.500 0.900 14.100 ;
        RECT 0.300 11.100 0.900 14.100 ;
        RECT 2.850 6.300 3.300 14.100 ;
        RECT 2.700 10.500 3.300 14.100 ;
        RECT 2.250 0.900 2.850 3.900 ;
        RECT 2.850 3.450 4.200 4.050 ;
        RECT 5.850 0.900 8.850 1.350 ;
        RECT 8.250 0.900 8.850 3.600 ;
        RECT 5.850 0.900 6.450 3.900 ;
        RECT 7.050 1.800 7.650 3.900 ;
        RECT 7.200 1.800 7.650 4.500 ;
        RECT 7.200 4.050 9.450 4.500 ;
        RECT 8.550 4.050 9.450 4.650 ;
        RECT 8.550 4.050 9.000 7.650 ;
        RECT 6.450 7.200 9.000 7.650 ;
        RECT 6.450 7.200 6.900 14.100 ;
        RECT 6.300 8.100 6.900 14.100 ;
      LAYER via ;
        RECT 3.000 6.450 3.300 6.750 ;
        RECT 3.000 3.600 3.300 3.900 ;
  END 
END HAX1

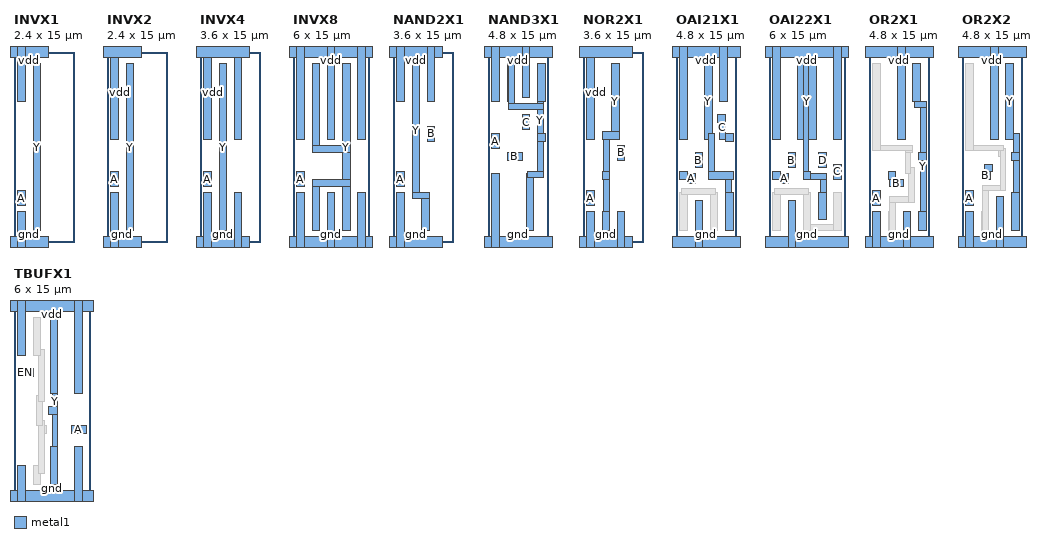
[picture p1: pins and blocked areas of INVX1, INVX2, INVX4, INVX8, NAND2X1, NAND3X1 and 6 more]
MACRO INVX1
  CLASS  CORE ;
  FOREIGN INVX1 0.000 0.000 ;
  ORIGIN 0.000 0.000 ;
  SIZE 2.400 BY 15.000 ;
  SYMMETRY X Y  ;
  SITE core ;
  PIN A
    DIRECTION INPUT ;
    PORT
      LAYER metal1 ;
        RECT 0.300 2.850 0.900 4.050 ;
    END
  END A
  PIN gnd
    DIRECTION INOUT ;
    USE GROUND ;
    SHAPE ABUTMENT ;
    PORT
      LAYER metal1 ;
        RECT 0.300 -0.450 0.900 2.400 ;
        RECT -0.300 -0.450 2.700 0.450 ;
    END
  END gnd
  PIN Y
    DIRECTION OUTPUT ;
    PORT
      LAYER metal1 ;
        RECT 1.500 0.900 2.100 14.100 ;
    END
  END Y
  PIN vdd
    DIRECTION INOUT ;
    USE POWER ;
    SHAPE ABUTMENT ;
    PORT
      LAYER metal1 ;
        RECT 0.300 11.100 0.900 15.450 ;
        RECT -0.300 14.550 2.700 15.450 ;
    END
  END vdd
END INVX1

MACRO INVX2
  CLASS  CORE ;
  FOREIGN INVX2 0.000 0.000 ;
  ORIGIN 0.000 0.000 ;
  SIZE 2.400 BY 15.000 ;
  SYMMETRY X Y  ;
  SITE core ;
  PIN A
    DIRECTION INPUT ;
    PORT
      LAYER metal1 ;
        RECT 0.300 4.350 0.900 5.550 ;
    END
  END A
  PIN gnd
    DIRECTION INOUT ;
    USE GROUND ;
    SHAPE ABUTMENT ;
    PORT
      LAYER metal1 ;
        RECT 0.300 -0.450 0.900 3.900 ;
        RECT -0.300 -0.450 2.700 0.450 ;
    END
  END gnd
  PIN Y
    DIRECTION OUTPUT ;
    PORT
      LAYER metal1 ;
        RECT 1.500 0.900 2.100 14.100 ;
    END
  END Y
  PIN vdd
    DIRECTION INOUT ;
    USE POWER ;
    SHAPE ABUTMENT ;
    PORT
      LAYER metal1 ;
        RECT 0.300 8.100 0.900 15.450 ;
        RECT -0.300 14.550 2.700 15.450 ;
    END
  END vdd
END INVX2

MACRO INVX4
  CLASS  CORE ;
  FOREIGN INVX4 0.000 0.000 ;
  ORIGIN 0.000 0.000 ;
  SIZE 3.600 BY 15.000 ;
  SYMMETRY X Y  ;
  SITE core ;
  PIN A
    DIRECTION INPUT ;
    PORT
      LAYER metal1 ;
        RECT 0.300 4.350 0.900 5.550 ;
    END
  END A
  PIN gnd
    DIRECTION INOUT ;
    USE GROUND ;
    SHAPE ABUTMENT ;
    PORT
      LAYER metal1 ;
        RECT 0.300 -0.450 0.900 3.900 ;
        RECT -0.300 -0.450 3.900 0.450 ;
        RECT 2.700 -0.450 3.300 3.900 ;
    END
  END gnd
  PIN Y
    DIRECTION OUTPUT ;
    PORT
      LAYER metal1 ;
        RECT 1.500 0.900 2.100 14.100 ;
    END
  END Y
  PIN vdd
    DIRECTION INOUT ;
    USE POWER ;
    SHAPE ABUTMENT ;
    PORT
      LAYER metal1 ;
        RECT 0.300 8.100 0.900 15.450 ;
        RECT -0.300 14.550 3.900 15.450 ;
        RECT 2.700 8.100 3.300 15.450 ;
    END
  END vdd
END INVX4

MACRO INVX8
  CLASS  CORE ;
  FOREIGN INVX8 0.000 0.000 ;
  ORIGIN 0.000 0.000 ;
  SIZE 6.000 BY 15.000 ;
  SYMMETRY X Y  ;
  SITE core ;
  PIN A
    DIRECTION INPUT ;
    PORT
      LAYER metal1 ;
        RECT 0.300 4.350 0.900 5.550 ;
    END
  END A
  PIN gnd
    DIRECTION INOUT ;
    USE GROUND ;
    SHAPE ABUTMENT ;
    PORT
      LAYER metal1 ;
        RECT 0.300 -0.450 0.900 3.900 ;
        RECT -0.300 -0.450 6.300 0.450 ;
        RECT 5.100 -0.450 5.700 3.900 ;
        RECT 2.700 -0.450 3.300 3.900 ;
    END
  END gnd
  PIN Y
    DIRECTION OUTPUT ;
    PORT
      LAYER metal1 ;
        RECT 1.500 0.900 2.100 4.950 ;
        RECT 3.900 0.900 4.500 14.100 ;
        RECT 1.500 7.050 4.500 7.650 ;
        RECT 1.500 4.350 4.500 4.950 ;
        RECT 1.500 7.050 2.100 14.100 ;
    END
  END Y
  PIN vdd
    DIRECTION INOUT ;
    USE POWER ;
    SHAPE ABUTMENT ;
    PORT
      LAYER metal1 ;
        RECT 0.300 8.100 0.900 15.450 ;
        RECT -0.300 14.550 6.300 15.450 ;
        RECT 5.100 8.100 5.700 15.450 ;
        RECT 2.700 8.100 3.300 15.450 ;
    END
  END vdd
END INVX8

MACRO NAND2X1
  CLASS  CORE ;
  FOREIGN NAND2X1 0.000 0.000 ;
  ORIGIN 0.000 0.000 ;
  SIZE 3.600 BY 15.000 ;
  SYMMETRY X Y  ;
  SITE core ;
  PIN A
    DIRECTION INPUT ;
    PORT
      LAYER metal1 ;
        RECT 0.300 4.350 0.900 5.550 ;
    END
  END A
  PIN B
    DIRECTION INPUT ;
    PORT
      LAYER metal1 ;
        RECT 2.700 7.950 3.300 9.150 ;
    END
  END B
  PIN gnd
    DIRECTION INOUT ;
    USE GROUND ;
    SHAPE ABUTMENT ;
    PORT
      LAYER metal1 ;
        RECT 0.300 -0.450 0.900 3.900 ;
        RECT -0.300 -0.450 3.900 0.450 ;
    END
  END gnd
  PIN Y
    DIRECTION OUTPUT ;
    PORT
      LAYER metal1 ;
        RECT 1.500 3.450 2.100 14.100 ;
        RECT 1.500 3.450 2.850 3.900 ;
        RECT 2.250 0.900 2.850 3.900 ;
    END
  END Y
  PIN vdd
    DIRECTION INOUT ;
    USE POWER ;
    SHAPE ABUTMENT ;
    PORT
      LAYER metal1 ;
        RECT 0.300 11.100 0.900 15.450 ;
        RECT -0.300 14.550 3.900 15.450 ;
        RECT 2.700 11.100 3.300 15.450 ;
    END
  END vdd
END NAND2X1

MACRO NAND3X1
  CLASS  CORE ;
  FOREIGN NAND3X1 0.000 0.000 ;
  ORIGIN 0.000 0.000 ;
  SIZE 4.800 BY 15.000 ;
  SYMMETRY X Y  ;
  SITE core ;
  PIN A
    DIRECTION INPUT ;
    PORT
      LAYER metal1 ;
        RECT 0.300 7.350 0.900 8.550 ;
    END
  END A
  PIN B
    DIRECTION INPUT ;
    PORT
      LAYER metal1 ;
        RECT 1.500 6.450 2.700 7.050 ;
    END
  END B
  PIN C
    DIRECTION INPUT ;
    PORT
      LAYER metal1 ;
        RECT 2.700 8.850 3.300 10.050 ;
    END
  END C
  PIN gnd
    DIRECTION INOUT ;
    USE GROUND ;
    SHAPE ABUTMENT ;
    PORT
      LAYER metal1 ;
        RECT 0.300 -0.450 0.900 5.400 ;
        RECT -0.300 -0.450 5.100 0.450 ;
    END
  END gnd
  PIN Y
    DIRECTION OUTPUT ;
    PORT
      LAYER metal1 ;
        RECT 1.650 10.500 2.100 14.100 ;
        RECT 3.900 11.100 4.500 14.100 ;
        RECT 3.900 7.950 4.500 8.550 ;
        RECT 3.900 5.100 4.350 14.100 ;
        RECT 1.650 10.500 4.350 10.950 ;
        RECT 3.150 5.100 4.350 5.550 ;
        RECT 3.000 0.900 3.600 5.400 ;
        RECT 1.500 11.100 2.100 14.100 ;
    END
  END Y
  PIN vdd
    DIRECTION INOUT ;
    USE POWER ;
    SHAPE ABUTMENT ;
    PORT
      LAYER metal1 ;
        RECT 0.300 11.100 0.900 15.450 ;
        RECT -0.300 14.550 5.100 15.450 ;
        RECT 2.700 11.400 3.300 15.450 ;
    END
  END vdd
END NAND3X1

MACRO NOR2X1
  CLASS  CORE ;
  FOREIGN NOR2X1 0.000 0.000 ;
  ORIGIN 0.000 0.000 ;
  SIZE 3.600 BY 15.000 ;
  SYMMETRY X Y  ;
  SITE core ;
  PIN A
    DIRECTION INPUT ;
    PORT
      LAYER metal1 ;
        RECT 0.300 2.850 0.900 4.050 ;
    END
  END A
  PIN B
    DIRECTION INPUT ;
    PORT
      LAYER metal1 ;
        RECT 2.700 6.450 3.300 7.650 ;
    END
  END B
  PIN gnd
    DIRECTION INOUT ;
    USE GROUND ;
    SHAPE ABUTMENT ;
    PORT
      LAYER metal1 ;
        RECT 0.300 -0.450 0.900 2.400 ;
        RECT -0.300 -0.450 3.900 0.450 ;
        RECT 2.700 -0.450 3.300 2.400 ;
    END
  END gnd
  PIN Y
    DIRECTION OUTPUT ;
    PORT
      LAYER metal1 ;
        RECT 1.500 0.900 2.100 2.400 ;
        RECT 2.250 8.100 2.850 14.100 ;
        RECT 1.500 8.100 2.850 8.700 ;
        RECT 1.650 0.900 2.100 8.700 ;
        RECT 1.500 4.950 2.100 5.550 ;
    END
  END Y
  PIN vdd
    DIRECTION INOUT ;
    USE POWER ;
    SHAPE ABUTMENT ;
    PORT
      LAYER metal1 ;
        RECT 0.300 8.100 0.900 15.450 ;
        RECT -0.300 14.550 3.900 15.450 ;
    END
  END vdd
END NOR2X1

MACRO OAI21X1
  CLASS  CORE ;
  FOREIGN OAI21X1 0.000 0.000 ;
  ORIGIN 0.000 0.000 ;
  SIZE 4.800 BY 15.000 ;
  SYMMETRY X Y  ;
  SITE core ;
  PIN A
    DIRECTION INPUT ;
    PORT
      LAYER metal1 ;
        RECT 0.300 4.950 0.900 5.550 ;
        RECT 0.900 4.650 1.500 5.400 ;
    END
  END A
  PIN B
    DIRECTION INPUT ;
    PORT
      LAYER metal1 ;
        RECT 1.500 5.850 2.100 7.050 ;
    END
  END B
  PIN C
    DIRECTION INPUT ;
    PORT
      LAYER metal1 ;
        RECT 3.450 8.100 3.900 10.050 ;
        RECT 3.900 7.950 4.500 8.550 ;
        RECT 3.300 9.450 3.900 10.050 ;
    END
  END C
  PIN gnd
    DIRECTION INOUT ;
    USE GROUND ;
    SHAPE ABUTMENT ;
    PORT
      LAYER metal1 ;
        RECT 1.500 -0.450 2.100 3.300 ;
        RECT -0.300 -0.450 5.100 0.450 ;
    END
  END gnd
  PIN Y
    DIRECTION OUTPUT ;
    PORT
      LAYER metal1 ;
        RECT 2.250 8.100 2.850 14.100 ;
        RECT 2.550 4.950 4.500 5.550 ;
        RECT 3.900 0.900 4.500 3.900 ;
        RECT 3.900 0.900 4.350 5.550 ;
        RECT 2.550 4.950 3.000 8.550 ;
    END
  END Y
  PIN vdd
    DIRECTION INOUT ;
    USE POWER ;
    SHAPE ABUTMENT ;
    PORT
      LAYER metal1 ;
        RECT 0.300 8.100 0.900 15.450 ;
        RECT -0.300 14.550 5.100 15.450 ;
        RECT 3.450 11.100 4.050 15.450 ;
    END
  END vdd
  OBS 
      LAYER metal1 ;
        RECT 0.300 0.900 0.900 3.900 ;
        RECT 2.700 0.900 3.300 3.900 ;
        RECT 0.450 3.750 3.150 4.200 ;
  END 
END OAI21X1

MACRO OAI22X1
  CLASS  CORE ;
  FOREIGN OAI22X1 0.000 0.000 ;
  ORIGIN 0.000 0.000 ;
  SIZE 6.000 BY 15.000 ;
  SYMMETRY X Y  ;
  SITE core ;
  PIN A
    DIRECTION INPUT ;
    PORT
      LAYER metal1 ;
        RECT 0.300 4.950 0.900 5.550 ;
        RECT 0.900 4.650 1.500 5.400 ;
    END
  END A
  PIN B
    DIRECTION INPUT ;
    PORT
      LAYER metal1 ;
        RECT 1.500 5.850 2.100 7.050 ;
    END
  END B
  PIN C
    DIRECTION INPUT ;
    PORT
      LAYER metal1 ;
        RECT 5.100 4.950 5.700 6.150 ;
    END
  END C
  PIN D
    DIRECTION INPUT ;
    PORT
      LAYER metal1 ;
        RECT 3.900 5.850 4.500 7.050 ;
    END
  END D
  PIN gnd
    DIRECTION INOUT ;
    USE GROUND ;
    SHAPE ABUTMENT ;
    PORT
      LAYER metal1 ;
        RECT 1.500 -0.450 2.100 3.300 ;
        RECT -0.300 -0.450 6.300 0.450 ;
    END
  END gnd
  PIN Y
    DIRECTION OUTPUT ;
    PORT
      LAYER metal1 ;
        RECT 2.700 4.950 3.150 14.100 ;
        RECT 2.700 4.950 4.500 5.400 ;
        RECT 4.050 1.800 4.500 5.400 ;
        RECT 3.900 1.800 4.500 3.900 ;
        RECT 2.250 8.100 3.750 14.100 ;
        RECT 2.700 4.950 3.300 5.550 ;
    END
  END Y
  PIN vdd
    DIRECTION INOUT ;
    USE POWER ;
    SHAPE ABUTMENT ;
    PORT
      LAYER metal1 ;
        RECT 0.300 8.100 0.900 15.450 ;
        RECT -0.300 14.550 6.300 15.450 ;
        RECT 5.100 8.100 5.700 15.450 ;
    END
  END vdd
  OBS 
      LAYER metal1 ;
        RECT 2.700 0.900 5.700 1.350 ;
        RECT 0.300 0.900 0.900 3.900 ;
        RECT 2.700 0.900 3.300 3.900 ;
        RECT 5.100 0.900 5.700 3.900 ;
        RECT 0.450 3.750 3.150 4.200 ;
  END 
END OAI22X1

MACRO OR2X1
  CLASS  CORE ;
  FOREIGN OR2X1 0.000 0.000 ;
  ORIGIN 0.000 0.000 ;
  SIZE 4.800 BY 15.000 ;
  SYMMETRY X Y  ;
  SITE core ;
  PIN A
    DIRECTION INPUT ;
    PORT
      LAYER metal1 ;
        RECT 0.300 2.850 0.900 4.050 ;
    END
  END A
  PIN B
    DIRECTION INPUT ;
    PORT
      LAYER metal1 ;
        RECT 1.500 4.950 2.100 5.550 ;
        RECT 1.650 4.350 2.700 4.950 ;
    END
  END B
  PIN gnd
    DIRECTION INOUT ;
    USE GROUND ;
    SHAPE ABUTMENT ;
    PORT
      LAYER metal1 ;
        RECT 0.300 -0.450 0.900 2.400 ;
        RECT -0.300 -0.450 5.100 0.450 ;
        RECT 2.700 -0.450 3.300 2.400 ;
    END
  END gnd
  PIN Y
    DIRECTION OUTPUT ;
    PORT
      LAYER metal1 ;
        RECT 3.900 0.900 4.500 2.400 ;
        RECT 4.050 0.900 4.500 11.100 ;
        RECT 3.450 11.100 4.050 14.100 ;
        RECT 3.600 10.650 4.500 11.100 ;
        RECT 3.900 6.450 4.500 7.050 ;
    END
  END Y
  PIN vdd
    DIRECTION INOUT ;
    USE POWER ;
    SHAPE ABUTMENT ;
    PORT
      LAYER metal1 ;
        RECT 2.250 8.100 2.850 15.450 ;
        RECT -0.300 14.550 5.100 15.450 ;
    END
  END vdd
  OBS 
      LAYER metal1 ;
        RECT 1.500 0.900 2.100 2.400 ;
        RECT 1.650 0.900 2.100 3.600 ;
        RECT 1.650 3.150 3.600 3.600 ;
        RECT 3.150 3.150 3.600 5.850 ;
        RECT 2.850 5.400 3.300 7.650 ;
        RECT 2.850 7.050 3.450 7.650 ;
        RECT 0.300 7.200 3.450 7.650 ;
        RECT 0.300 7.200 0.900 14.100 ;
  END 
END OR2X1

MACRO OR2X2
  CLASS  CORE ;
  FOREIGN OR2X2 0.000 0.000 ;
  ORIGIN 0.000 0.000 ;
  SIZE 4.800 BY 15.000 ;
  SYMMETRY X Y  ;
  SITE core ;
  PIN A
    DIRECTION INPUT ;
    PORT
      LAYER metal1 ;
        RECT 0.300 2.850 0.900 4.050 ;
    END
  END A
  PIN B
    DIRECTION INPUT ;
    PORT
      LAYER metal1 ;
        RECT 1.500 4.950 2.250 5.550 ;
        RECT 1.800 5.550 2.400 6.150 ;
    END
  END B
  PIN gnd
    DIRECTION INOUT ;
    USE GROUND ;
    SHAPE ABUTMENT ;
    PORT
      LAYER metal1 ;
        RECT 0.300 -0.450 0.900 2.400 ;
        RECT -0.300 -0.450 5.100 0.450 ;
        RECT 2.700 -0.450 3.300 3.600 ;
    END
  END gnd
  PIN Y
    DIRECTION OUTPUT ;
    PORT
      LAYER metal1 ;
        RECT 3.900 0.900 4.500 3.900 ;
        RECT 4.050 0.900 4.500 8.550 ;
        RECT 3.450 8.100 4.050 14.100 ;
        RECT 3.900 6.450 4.500 7.050 ;
    END
  END Y
  PIN vdd
    DIRECTION INOUT ;
    USE POWER ;
    SHAPE ABUTMENT ;
    PORT
      LAYER metal1 ;
        RECT 2.250 8.100 2.850 15.450 ;
        RECT -0.300 14.550 5.100 15.450 ;
    END
  END vdd
  OBS 
      LAYER metal1 ;
        RECT 1.500 0.900 2.100 2.400 ;
        RECT 1.650 0.900 2.100 4.500 ;
        RECT 1.650 4.050 3.450 4.500 ;
        RECT 2.850 6.750 3.450 7.350 ;
        RECT 3.000 4.050 3.450 7.350 ;
        RECT 0.300 7.200 3.300 7.650 ;
        RECT 0.300 7.200 0.900 14.100 ;
  END 
END OR2X2

MACRO TBUFX1
  CLASS  CORE ;
  FOREIGN TBUFX1 0.000 0.000 ;
  ORIGIN 0.000 0.000 ;
  SIZE 6.000 BY 15.000 ;
  SYMMETRY X Y  ;
  SITE core ;
  PIN A
    DIRECTION INPUT ;
    PORT
      LAYER metal1 ;
        RECT 4.500 4.950 5.700 5.550 ;
    END
  END A
  PIN EN
    DIRECTION INPUT ;
    PORT
      LAYER metal1 ;
        RECT 0.300 9.450 1.500 10.050 ;
    END
  END EN
  PIN gnd
    DIRECTION INOUT ;
    USE GROUND ;
    SHAPE ABUTMENT ;
    PORT
      LAYER metal1 ;
        RECT 0.300 -0.450 0.900 2.400 ;
        RECT -0.300 -0.450 6.300 0.450 ;
        RECT 4.800 -0.450 5.400 3.900 ;
    END
  END gnd
  PIN Y
    DIRECTION OUTPUT TRISTATE ;
    PORT
      LAYER metal1 ;
        RECT 2.850 0.900 3.450 3.900 ;
        RECT 2.850 8.100 3.450 14.100 ;
        RECT 3.000 0.900 3.450 14.100 ;
        RECT 2.700 6.450 3.450 7.050 ;
    END
  END Y
  PIN vdd
    DIRECTION INOUT ;
    USE POWER ;
    SHAPE ABUTMENT ;
    PORT
      LAYER metal1 ;
        RECT 0.300 11.100 0.900 15.450 ;
        RECT -0.300 14.550 6.300 15.450 ;
        RECT 4.800 8.100 5.400 15.450 ;
    END
  END vdd
  OBS 
      LAYER metal1 ;
        RECT 1.500 0.900 2.100 2.400 ;
        RECT 1.950 4.950 2.550 5.550 ;
        RECT 1.950 1.800 2.400 6.000 ;
        RECT 1.800 5.550 2.250 7.950 ;
        RECT 1.950 7.500 2.400 11.550 ;
        RECT 1.500 11.100 2.100 14.100 ;
  END 
END TBUFX1

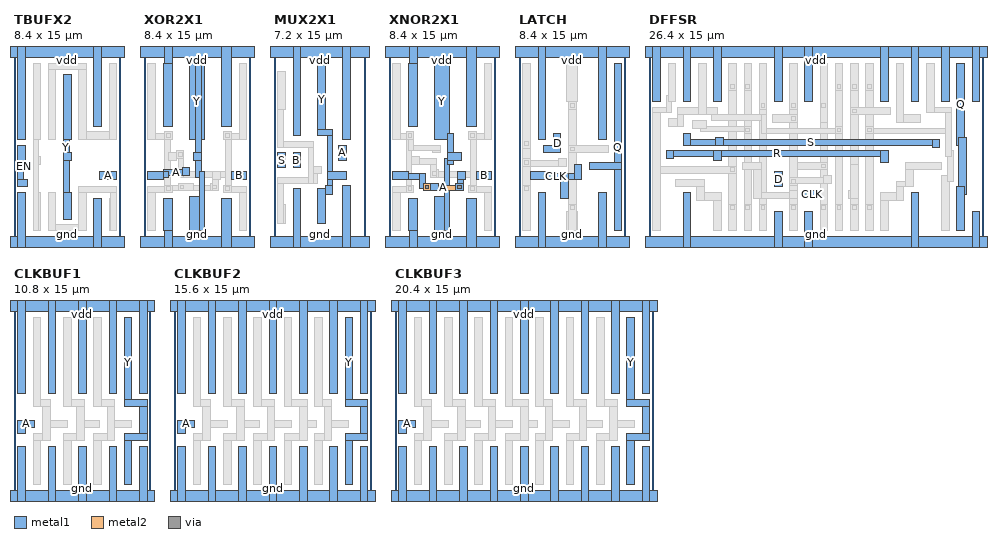
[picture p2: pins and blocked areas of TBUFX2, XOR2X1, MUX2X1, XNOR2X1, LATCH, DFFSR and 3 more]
MACRO TBUFX2
  CLASS  CORE ;
  FOREIGN TBUFX2 0.000 0.000 ;
  ORIGIN 0.000 0.000 ;
  SIZE 8.400 BY 15.000 ;
  SYMMETRY X Y  ;
  SITE core ;
  PIN A
    DIRECTION INPUT ;
    PORT
      LAYER metal1 ;
        RECT 6.750 4.950 8.100 5.550 ;
    END
  END A
  PIN EN
    DIRECTION INPUT ;
    PORT
      LAYER metal1 ;
        RECT 0.300 4.350 0.750 7.650 ;
        RECT 0.300 4.350 1.050 4.950 ;
        RECT 0.300 6.450 0.900 7.650 ;
    END
  END EN
  PIN gnd
    DIRECTION INOUT ;
    USE GROUND ;
    SHAPE ABUTMENT ;
    PORT
      LAYER metal1 ;
        RECT 0.300 -0.450 0.900 3.900 ;
        RECT -0.300 -0.450 8.700 0.450 ;
        RECT 6.300 -0.450 6.900 3.450 ;
    END
  END gnd
  PIN Y
    DIRECTION OUTPUT TRISTATE ;
    PORT
      LAYER metal1 ;
        RECT 3.900 1.800 4.350 13.200 ;
        RECT 3.900 8.100 4.500 13.200 ;
        RECT 3.900 6.450 4.500 7.050 ;
        RECT 3.900 1.800 4.500 3.900 ;
    END
  END Y
  PIN vdd
    DIRECTION INOUT ;
    USE POWER ;
    SHAPE ABUTMENT ;
    PORT
      LAYER metal1 ;
        RECT 0.300 8.100 0.900 15.450 ;
        RECT -0.300 14.550 8.700 15.450 ;
        RECT 6.300 9.150 6.900 15.450 ;
    END
  END vdd
  OBS 
      LAYER metal1 ;
        RECT 1.500 0.900 2.100 3.900 ;
        RECT 1.500 6.150 2.100 6.750 ;
        RECT 1.500 0.900 1.950 14.100 ;
        RECT 1.500 8.100 2.100 14.100 ;
        RECT 5.100 8.100 8.100 8.700 ;
        RECT 2.700 8.100 3.300 14.100 ;
        RECT 5.100 8.100 5.700 14.100 ;
        RECT 2.700 13.650 5.700 14.100 ;
        RECT 7.500 8.100 8.100 14.100 ;
        RECT 2.700 0.900 5.700 1.350 ;
        RECT 7.500 0.900 8.100 3.450 ;
        RECT 5.100 0.900 5.700 4.350 ;
        RECT 2.700 0.900 3.300 3.900 ;
        RECT 7.650 0.900 8.100 4.350 ;
        RECT 5.100 3.900 8.100 4.350 ;
  END 
END TBUFX2

MACRO XOR2X1
  CLASS  CORE ;
  FOREIGN XOR2X1 0.000 0.000 ;
  ORIGIN 0.000 0.000 ;
  SIZE 8.400 BY 15.000 ;
  SYMMETRY X Y  ;
  SITE core ;
  PIN A
    DIRECTION INPUT ;
    PORT
      LAYER metal1 ;
        RECT 0.300 4.950 1.500 5.550 ;
        RECT 3.000 5.250 3.600 5.850 ;
        RECT 1.500 5.250 3.600 5.700 ;
        RECT 0.300 5.100 1.950 5.550 ;
    END
  END A
  PIN B
    DIRECTION INPUT ;
    PORT
      LAYER metal1 ;
        RECT 6.900 4.950 8.100 5.550 ;
    END
  END B
  PIN gnd
    DIRECTION INOUT ;
    USE GROUND ;
    SHAPE ABUTMENT ;
    PORT
      LAYER metal1 ;
        RECT 1.650 -0.450 2.250 3.450 ;
        RECT -0.300 -0.450 8.700 0.450 ;
        RECT 6.150 -0.450 6.900 3.450 ;
        RECT 1.500 0.900 2.250 3.450 ;
    END
  END gnd
  PIN Y
    DIRECTION OUTPUT ;
    PORT
      LAYER metal1 ;
        RECT 3.900 6.450 4.500 7.050 ;
        RECT 3.600 8.100 4.800 14.100 ;
        RECT 4.350 0.900 4.800 5.550 ;
        RECT 4.050 5.100 4.500 14.100 ;
        RECT 3.600 0.900 4.800 3.600 ;
    END
  END Y
  PIN vdd
    DIRECTION INOUT ;
    USE POWER ;
    SHAPE ABUTMENT ;
    PORT
      LAYER metal1 ;
        RECT 1.500 9.150 2.250 14.100 ;
        RECT -0.300 14.550 8.700 15.450 ;
        RECT 6.150 9.150 6.900 15.450 ;
        RECT 1.650 9.150 2.250 15.450 ;
    END
  END vdd
  OBS 
      LAYER metal2 ;
        RECT 1.650 3.900 2.250 4.500 ;
        RECT 1.650 4.050 5.850 4.500 ;
        RECT 2.700 4.050 3.300 4.650 ;
        RECT 5.250 4.050 5.850 4.650 ;
        RECT 1.650 3.900 2.100 8.700 ;
        RECT 1.650 8.100 2.250 8.700 ;
        RECT 6.300 3.900 6.900 4.500 ;
        RECT 2.700 5.100 6.900 5.550 ;
        RECT 2.700 5.100 3.150 7.200 ;
        RECT 2.550 6.600 3.150 7.200 ;
        RECT 6.450 3.900 6.900 8.700 ;
        RECT 6.300 8.100 6.900 8.700 ;
      LAYER metal1 ;
        RECT 0.300 8.100 2.250 8.550 ;
        RECT 1.650 8.100 2.250 8.700 ;
        RECT 0.300 8.100 0.900 14.100 ;
        RECT 0.300 0.900 0.900 4.350 ;
        RECT 0.300 3.900 2.250 4.350 ;
        RECT 1.650 3.900 2.250 4.500 ;
        RECT 1.950 6.450 2.550 7.050 ;
        RECT 2.550 6.600 3.150 7.200 ;
        RECT 2.700 4.050 3.900 4.650 ;
        RECT 5.250 4.050 5.850 4.650 ;
        RECT 5.400 4.050 5.850 5.550 ;
        RECT 5.400 4.950 6.000 5.550 ;
        RECT 6.300 8.100 8.100 8.550 ;
        RECT 6.300 8.100 6.900 8.700 ;
        RECT 7.500 8.100 8.100 14.100 ;
        RECT 7.500 0.900 8.100 4.350 ;
        RECT 6.300 3.900 8.100 4.350 ;
        RECT 6.300 3.900 6.900 4.500 ;
      LAYER via ;
        RECT 1.800 8.250 2.100 8.550 ;
        RECT 1.800 4.050 2.100 4.350 ;
        RECT 2.700 6.750 3.000 7.050 ;
        RECT 2.850 4.200 3.150 4.500 ;
        RECT 5.400 4.200 5.700 4.500 ;
        RECT 6.450 8.250 6.750 8.550 ;
        RECT 6.450 4.050 6.750 4.350 ;
  END 
END XOR2X1

MACRO MUX2X1
  CLASS  CORE ;
  FOREIGN MUX2X1 0.000 0.000 ;
  ORIGIN 0.000 0.000 ;
  SIZE 7.200 BY 15.000 ;
  SYMMETRY X Y  ;
  SITE core ;
  PIN A
    DIRECTION INPUT ;
    PORT
      LAYER metal1 ;
        RECT 5.100 6.450 5.700 7.650 ;
    END
  END A
  PIN B
    DIRECTION INPUT ;
    PORT
      LAYER metal1 ;
        RECT 1.500 5.850 2.100 7.050 ;
    END
  END B
  PIN S
    DIRECTION INPUT ;
    PORT
      LAYER metal1 ;
        RECT 0.300 5.850 0.900 7.050 ;
    END
  END S
  PIN gnd
    DIRECTION INOUT ;
    USE GROUND ;
    SHAPE ABUTMENT ;
    PORT
      LAYER metal1 ;
        RECT 1.500 -0.450 2.100 4.200 ;
        RECT -0.300 -0.450 7.500 0.450 ;
        RECT 5.400 -0.450 6.000 4.500 ;
    END
  END gnd
  PIN Y
    DIRECTION OUTPUT ;
    PORT
      LAYER metal1 ;
        RECT 3.450 1.500 4.050 4.200 ;
        RECT 4.200 4.950 5.700 5.550 ;
        RECT 3.450 8.400 4.650 8.850 ;
        RECT 4.200 3.750 4.650 8.850 ;
        RECT 4.050 3.750 4.650 4.500 ;
        RECT 3.450 8.400 4.050 14.100 ;
    END
  END Y
  PIN vdd
    DIRECTION INOUT ;
    USE POWER ;
    SHAPE ABUTMENT ;
    PORT
      LAYER metal1 ;
        RECT 1.500 8.400 2.100 15.450 ;
        RECT -0.300 14.550 7.500 15.450 ;
        RECT 5.400 8.100 6.000 15.450 ;
    END
  END vdd
  OBS 
      LAYER metal1 ;
        RECT 0.300 1.500 0.900 3.000 ;
        RECT 0.300 1.500 0.750 5.100 ;
        RECT 0.300 4.650 3.450 5.100 ;
        RECT 2.700 4.650 3.450 6.000 ;
        RECT 2.700 5.400 3.750 6.000 ;
        RECT 2.700 4.650 3.150 7.950 ;
        RECT 0.300 7.500 3.150 7.950 ;
        RECT 0.300 7.500 0.750 13.500 ;
        RECT 0.300 10.500 0.900 13.500 ;
  END 
END MUX2X1

MACRO XNOR2X1
  CLASS  CORE ;
  FOREIGN XNOR2X1 0.000 0.000 ;
  ORIGIN 0.000 0.000 ;
  SIZE 8.400 BY 15.000 ;
  SYMMETRY X Y  ;
  SITE core ;
  PIN A
    DIRECTION INPUT ;
    PORT
      LAYER metal2 ;
        RECT 2.700 4.050 3.300 4.650 ;
        RECT 5.250 4.050 5.850 4.650 ;
        RECT 2.700 4.050 5.850 4.500 ;
      LAYER via ;
        RECT 2.850 4.200 3.150 4.500 ;
        RECT 5.400 4.200 5.700 4.500 ;
      LAYER metal1 ;
        RECT 0.300 4.950 1.500 5.550 ;
        RECT 5.400 4.950 6.000 5.550 ;
        RECT 5.400 4.050 5.850 5.550 ;
        RECT 5.250 4.050 5.850 4.650 ;
        RECT 2.700 4.050 3.900 4.650 ;
        RECT 0.300 4.950 2.850 5.400 ;
        RECT 2.400 4.200 2.850 5.400 ;
    END
  END A
  PIN B
    DIRECTION INPUT ;
    PORT
      LAYER metal1 ;
        RECT 6.900 4.950 8.100 5.550 ;
    END
  END B
  PIN gnd
    DIRECTION INOUT ;
    USE GROUND ;
    SHAPE ABUTMENT ;
    PORT
      LAYER metal1 ;
        RECT 1.650 -0.450 2.250 3.450 ;
        RECT -0.300 -0.450 8.700 0.450 ;
        RECT 6.150 -0.450 6.900 3.450 ;
        RECT 1.500 0.900 2.250 3.450 ;
    END
  END gnd
  PIN Y
    DIRECTION OUTPUT ;
    PORT
      LAYER metal1 ;
        RECT 3.600 0.900 4.800 3.600 ;
        RECT 4.650 6.450 5.700 7.050 ;
        RECT 4.650 6.150 5.100 8.550 ;
        RECT 3.600 8.100 4.800 14.100 ;
        RECT 4.350 0.900 4.800 6.600 ;
    END
  END Y
  PIN vdd
    DIRECTION INOUT ;
    USE POWER ;
    SHAPE ABUTMENT ;
    PORT
      LAYER metal1 ;
        RECT 1.500 9.150 2.250 14.100 ;
        RECT -0.300 14.550 8.700 15.450 ;
        RECT 6.150 9.150 6.900 15.450 ;
        RECT 1.650 9.150 2.250 15.450 ;
    END
  END vdd
  OBS 
      LAYER metal2 ;
        RECT 1.350 3.900 1.950 4.500 ;
        RECT 1.350 3.900 1.800 8.700 ;
        RECT 1.350 8.100 1.950 8.700 ;
        RECT 6.300 3.900 6.900 4.500 ;
        RECT 3.300 5.100 6.900 5.550 ;
        RECT 3.300 5.100 3.900 5.700 ;
        RECT 6.450 3.900 6.900 8.700 ;
        RECT 6.300 8.100 6.900 8.700 ;
      LAYER metal1 ;
        RECT 0.300 0.900 0.900 4.350 ;
        RECT 0.300 3.900 1.950 4.350 ;
        RECT 1.350 3.900 1.950 4.500 ;
        RECT 3.300 5.100 3.900 5.700 ;
        RECT 3.300 5.100 3.750 6.600 ;
        RECT 1.800 6.150 3.750 6.600 ;
        RECT 1.800 6.150 2.400 6.750 ;
        RECT 3.450 7.050 4.050 7.650 ;
        RECT 1.500 7.200 4.050 7.650 ;
        RECT 0.300 8.100 1.950 8.550 ;
        RECT 1.500 7.200 1.950 8.700 ;
        RECT 1.350 8.100 1.950 8.700 ;
        RECT 0.300 8.100 0.900 14.100 ;
        RECT 6.300 8.100 8.100 8.550 ;
        RECT 6.300 8.100 6.900 8.700 ;
        RECT 7.500 8.100 8.100 14.100 ;
        RECT 7.500 0.900 8.100 4.350 ;
        RECT 6.300 3.900 8.100 4.350 ;
        RECT 6.300 3.900 6.900 4.500 ;
      LAYER via ;
        RECT 1.500 8.250 1.800 8.550 ;
        RECT 1.500 4.050 1.800 4.350 ;
        RECT 3.450 5.250 3.750 5.550 ;
        RECT 6.450 8.250 6.750 8.550 ;
        RECT 6.450 4.050 6.750 4.350 ;
  END 
END XNOR2X1

MACRO LATCH
  CLASS  CORE ;
  FOREIGN LATCH 0.000 0.000 ;
  ORIGIN 0.000 0.000 ;
  SIZE 8.400 BY 15.000 ;
  SYMMETRY X Y  ;
  SITE core ;
  PIN Q
    DIRECTION OUTPUT ;
    PORT
      LAYER metal1 ;
        RECT 5.550 5.700 8.100 6.300 ;
        RECT 7.500 0.900 8.100 14.100 ;
    END
  END Q
  PIN CLK
    DIRECTION INPUT ;
    USE CLOCK ;
    PORT
      LAYER metal1 ;
        RECT 0.900 4.950 2.100 5.550 ;
        RECT 4.350 4.950 4.950 6.150 ;
        RECT 0.900 4.950 4.950 5.400 ;
        RECT 3.300 3.450 3.900 5.400 ;
    END
  END CLK
  PIN D
    DIRECTION INPUT ;
    PORT
      LAYER metal1 ;
        RECT 1.950 7.050 3.300 7.650 ;
        RECT 2.700 7.050 3.300 8.550 ;
    END
  END D
  PIN gnd
    DIRECTION INOUT ;
    USE GROUND ;
    SHAPE ABUTMENT ;
    PORT
      LAYER metal1 ;
        RECT 1.500 -0.450 2.100 3.900 ;
        RECT -0.300 -0.450 8.700 0.450 ;
        RECT 6.300 -0.450 6.900 3.900 ;
    END
  END gnd
  PIN vdd
    DIRECTION INOUT ;
    USE POWER ;
    SHAPE ABUTMENT ;
    PORT
      LAYER metal1 ;
        RECT 1.500 8.100 2.100 15.450 ;
        RECT -0.300 14.550 8.700 15.450 ;
        RECT 6.300 8.100 6.900 15.450 ;
    END
  END vdd
  OBS 
      LAYER metal2 ;
        RECT 0.300 3.900 0.900 8.100 ;
        RECT 3.900 2.400 4.500 11.100 ;
      LAYER metal1 ;
        RECT 0.300 7.350 0.900 14.100 ;
        RECT 0.300 0.900 0.900 4.500 ;
        RECT 0.300 6.000 3.750 6.450 ;
        RECT 0.300 6.000 0.900 6.600 ;
        RECT 3.150 6.000 3.750 6.600 ;
        RECT 3.900 10.500 4.500 14.100 ;
        RECT 3.750 11.100 4.650 14.100 ;
        RECT 3.750 0.900 4.650 2.400 ;
        RECT 3.900 0.900 4.500 3.000 ;
        RECT 3.900 7.050 7.050 7.650 ;
      LAYER via ;
        RECT 0.450 7.650 0.750 7.950 ;
        RECT 0.450 6.150 0.750 6.450 ;
        RECT 0.450 4.050 0.750 4.350 ;
        RECT 4.050 10.650 4.350 10.950 ;
        RECT 4.050 7.200 4.350 7.500 ;
        RECT 4.050 2.550 4.350 2.850 ;
  END 
END LATCH

MACRO DFFSR
  CLASS  CORE ;
  FOREIGN DFFSR 0.000 0.000 ;
  ORIGIN 0.000 0.000 ;
  SIZE 26.400 BY 15.000 ;
  SYMMETRY X Y  ;
  SITE core ;
  PIN Q
    DIRECTION OUTPUT ;
    PORT
      LAYER metal1 ;
        RECT 24.300 0.900 24.900 4.350 ;
        RECT 24.450 3.750 25.050 8.250 ;
        RECT 24.300 7.650 24.900 14.100 ;
    END
  END Q
  PIN CLK
    DIRECTION INPUT ;
    USE CLOCK ;
    PORT
      LAYER metal1 ;
        RECT 12.300 3.450 13.500 4.050 ;
    END
  END CLK
  PIN R
    DIRECTION INPUT ;
    PORT
      LAYER metal1 ;
        RECT 1.350 6.600 1.950 7.200 ;
        RECT 1.350 6.750 18.900 7.200 ;
        RECT 18.300 6.300 18.900 7.200 ;
        RECT 5.100 6.450 5.700 7.200 ;
    END
  END R
  PIN S
    DIRECTION INPUT ;
    PORT
      LAYER metal1 ;
        RECT 2.700 7.650 3.300 8.550 ;
        RECT 2.700 7.650 22.950 8.100 ;
        RECT 22.350 7.500 22.950 8.100 ;
        RECT 5.250 7.650 5.850 8.250 ;
    END
  END S
  PIN D
    DIRECTION INPUT ;
    PORT
      LAYER metal1 ;
        RECT 9.900 4.350 10.500 5.550 ;
    END
  END D
  PIN gnd
    DIRECTION INOUT ;
    USE GROUND ;
    SHAPE ABUTMENT ;
    PORT
      LAYER metal1 ;
        RECT 2.700 -0.450 3.300 3.900 ;
        RECT -0.300 -0.450 26.700 0.450 ;
        RECT 25.500 -0.450 26.100 2.400 ;
        RECT 20.700 -0.450 21.300 3.900 ;
        RECT 12.300 -0.450 12.900 2.400 ;
        RECT 9.900 -0.450 10.500 2.400 ;
    END
  END gnd
  PIN vdd
    DIRECTION INOUT ;
    USE POWER ;
    SHAPE ABUTMENT ;
    PORT
      LAYER metal1 ;
        RECT 0.300 11.100 0.900 15.450 ;
        RECT -0.300 14.550 26.700 15.450 ;
        RECT 25.500 11.100 26.100 15.450 ;
        RECT 23.100 11.100 23.700 15.450 ;
        RECT 20.700 11.100 21.300 15.450 ;
        RECT 18.300 11.100 18.900 15.450 ;
        RECT 12.300 11.100 12.900 15.450 ;
        RECT 9.900 11.100 10.500 15.450 ;
        RECT 5.100 11.100 5.700 15.450 ;
        RECT 2.700 11.100 3.300 15.450 ;
    END
  END vdd
  OBS 
      LAYER metal2 ;
        RECT 6.300 2.400 6.900 12.600 ;
        RECT 7.500 2.400 8.100 12.600 ;
        RECT 8.700 2.400 9.300 11.100 ;
        RECT 11.100 2.400 11.700 11.100 ;
        RECT 13.500 2.400 14.100 11.100 ;
        RECT 14.700 2.400 15.300 12.600 ;
        RECT 15.900 2.400 16.500 12.600 ;
        RECT 17.100 2.400 17.700 12.600 ;
      LAYER metal1 ;
        RECT 5.100 0.900 5.700 3.900 ;
        RECT 3.750 3.300 5.700 3.900 ;
        RECT 3.750 3.300 4.350 4.950 ;
        RECT 2.100 4.350 4.350 4.950 ;
        RECT 6.300 12.000 6.900 14.100 ;
        RECT 0.300 5.400 6.900 6.000 ;
        RECT 0.300 0.900 0.900 10.650 ;
        RECT 0.300 10.200 1.800 10.650 ;
        RECT 1.350 10.200 1.800 11.550 ;
        RECT 1.500 11.100 2.100 14.100 ;
        RECT 6.300 0.900 6.900 3.000 ;
        RECT 7.500 12.000 8.100 14.100 ;
        RECT 4.050 8.700 8.100 9.150 ;
        RECT 7.500 8.550 8.100 9.150 ;
        RECT 3.450 9.000 4.500 9.600 ;
        RECT 7.500 0.900 8.100 3.000 ;
        RECT 8.700 10.500 9.300 14.100 ;
        RECT 8.700 0.900 9.300 3.000 ;
        RECT 11.100 10.500 11.700 14.100 ;
        RECT 9.750 9.450 11.700 10.050 ;
        RECT 8.250 3.450 11.700 3.900 ;
        RECT 11.100 3.450 11.700 4.050 ;
        RECT 8.250 3.450 8.850 6.300 ;
        RECT 7.350 5.700 8.850 6.300 ;
        RECT 11.100 0.900 11.700 3.000 ;
        RECT 13.500 9.450 14.100 14.100 ;
        RECT 11.700 5.700 14.100 6.300 ;
        RECT 13.500 0.900 14.100 3.000 ;
        RECT 11.100 4.500 11.700 5.100 ;
        RECT 11.100 4.650 14.400 5.100 ;
        RECT 13.800 4.650 14.400 5.250 ;
        RECT 14.700 12.000 15.300 14.100 ;
        RECT 8.850 8.550 15.300 9.000 ;
        RECT 14.700 8.550 15.300 9.150 ;
        RECT 1.500 9.150 2.700 9.750 ;
        RECT 2.250 9.150 2.700 10.650 ;
        RECT 4.950 9.600 9.300 10.050 ;
        RECT 8.850 8.550 9.300 10.050 ;
        RECT 2.250 10.050 5.400 10.650 ;
        RECT 3.900 10.050 4.500 14.100 ;
        RECT 14.700 0.900 15.300 3.000 ;
        RECT 15.900 12.000 16.500 14.100 ;
        RECT 15.750 3.450 16.500 4.050 ;
        RECT 15.900 3.450 16.500 6.150 ;
        RECT 15.900 0.900 16.500 3.000 ;
        RECT 17.100 12.000 17.700 14.100 ;
        RECT 17.100 0.900 17.700 3.000 ;
        RECT 15.900 10.050 19.050 10.650 ;
        RECT 19.500 9.450 21.450 10.050 ;
        RECT 19.500 9.450 20.100 14.100 ;
        RECT 18.300 0.900 18.900 3.900 ;
        RECT 18.300 3.300 20.100 3.900 ;
        RECT 19.500 3.300 20.100 4.800 ;
        RECT 19.500 4.350 20.850 4.800 ;
        RECT 20.250 4.350 20.850 6.300 ;
        RECT 20.250 5.700 23.100 6.300 ;
        RECT 23.100 0.900 23.700 5.250 ;
        RECT 23.550 4.800 24.000 7.200 ;
        RECT 17.100 8.550 23.850 9.000 ;
        RECT 17.100 8.550 17.700 9.150 ;
        RECT 23.400 6.750 23.850 10.650 ;
        RECT 21.900 10.200 23.850 10.650 ;
        RECT 21.900 10.200 22.500 14.100 ;
      LAYER via ;
        RECT 6.450 12.150 6.750 12.450 ;
        RECT 6.450 5.550 6.750 5.850 ;
        RECT 6.450 2.550 6.750 2.850 ;
        RECT 7.650 12.150 7.950 12.450 ;
        RECT 7.650 8.700 7.950 9.000 ;
        RECT 7.650 2.550 7.950 2.850 ;
        RECT 8.850 10.650 9.150 10.950 ;
        RECT 8.850 2.550 9.150 2.850 ;
        RECT 11.250 10.650 11.550 10.950 ;
        RECT 11.250 9.600 11.550 9.900 ;
        RECT 11.250 4.650 11.550 4.950 ;
        RECT 11.250 2.550 11.550 2.850 ;
        RECT 13.650 10.650 13.950 10.950 ;
        RECT 13.650 5.850 13.950 6.150 ;
        RECT 13.650 2.550 13.950 2.850 ;
        RECT 14.850 12.150 15.150 12.450 ;
        RECT 14.850 8.700 15.150 9.000 ;
        RECT 14.850 2.550 15.150 2.850 ;
        RECT 16.050 12.150 16.350 12.450 ;
        RECT 16.050 10.200 16.350 10.500 ;
        RECT 16.050 2.550 16.350 2.850 ;
        RECT 17.250 12.150 17.550 12.450 ;
        RECT 17.250 8.700 17.550 9.000 ;
        RECT 17.250 2.550 17.550 2.850 ;
  END 
END DFFSR

MACRO CLKBUF1
  CLASS  CORE ;
  FOREIGN CLKBUF1 0.000 0.000 ;
  ORIGIN 0.000 0.000 ;
  SIZE 10.800 BY 15.000 ;
  SYMMETRY X Y  ;
  SITE core ;
  PIN A
    DIRECTION INPUT ;
    PORT
      LAYER metal1 ;
        RECT 0.300 4.950 0.900 6.000 ;
        RECT 0.300 5.400 1.650 6.000 ;
    END
  END A
  PIN gnd
    DIRECTION INOUT ;
    USE GROUND ;
    SHAPE ABUTMENT ;
    PORT
      LAYER metal1 ;
        RECT 0.300 -0.450 0.900 3.900 ;
        RECT -0.300 -0.450 11.100 0.450 ;
        RECT 9.900 -0.450 10.500 3.900 ;
        RECT 7.500 -0.450 8.100 3.900 ;
        RECT 5.100 -0.450 5.700 3.900 ;
        RECT 2.700 -0.450 3.300 3.900 ;
    END
  END gnd
  PIN Y
    DIRECTION OUTPUT ;
    PORT
      LAYER metal1 ;
        RECT 8.700 0.900 9.300 4.950 ;
        RECT 8.700 7.050 10.500 7.650 ;
        RECT 9.900 4.350 10.500 7.650 ;
        RECT 8.700 4.350 10.500 4.950 ;
        RECT 8.700 7.050 9.300 14.100 ;
    END
  END Y
  PIN vdd
    DIRECTION INOUT ;
    USE POWER ;
    SHAPE ABUTMENT ;
    PORT
      LAYER metal1 ;
        RECT 0.300 8.100 0.900 15.450 ;
        RECT -0.300 14.550 11.100 15.450 ;
        RECT 9.900 8.100 10.500 15.450 ;
        RECT 7.500 8.100 8.100 15.450 ;
        RECT 5.100 8.100 5.700 15.450 ;
        RECT 2.700 8.100 3.300 15.450 ;
    END
  END vdd
  OBS 
      LAYER metal1 ;
        RECT 1.500 0.900 2.100 4.950 ;
        RECT 1.500 4.350 2.850 4.950 ;
        RECT 2.250 5.400 4.200 6.000 ;
        RECT 2.250 4.350 2.850 7.650 ;
        RECT 1.500 7.050 2.850 7.650 ;
        RECT 1.500 7.050 2.100 14.100 ;
        RECT 3.900 0.900 4.500 4.950 ;
        RECT 3.900 4.350 5.550 4.950 ;
        RECT 4.950 5.400 6.750 6.000 ;
        RECT 4.950 4.350 5.550 7.650 ;
        RECT 3.900 7.050 5.550 7.650 ;
        RECT 3.900 7.050 4.500 14.100 ;
        RECT 6.300 0.900 6.900 4.950 ;
        RECT 6.300 4.350 7.950 4.950 ;
        RECT 7.350 5.400 9.300 6.000 ;
        RECT 7.350 4.350 7.950 7.650 ;
        RECT 6.300 7.050 7.950 7.650 ;
        RECT 6.300 7.050 6.900 14.100 ;
  END 
END CLKBUF1

MACRO CLKBUF2
  CLASS  CORE ;
  FOREIGN CLKBUF2 0.000 0.000 ;
  ORIGIN 0.000 0.000 ;
  SIZE 15.600 BY 15.000 ;
  SYMMETRY X Y  ;
  SITE core ;
  PIN A
    DIRECTION INPUT ;
    PORT
      LAYER metal1 ;
        RECT 0.300 4.950 0.900 6.000 ;
        RECT 0.300 5.400 1.650 6.000 ;
    END
  END A
  PIN gnd
    DIRECTION INOUT ;
    USE GROUND ;
    SHAPE ABUTMENT ;
    PORT
      LAYER metal1 ;
        RECT 0.300 -0.450 0.900 3.900 ;
        RECT -0.300 -0.450 15.900 0.450 ;
        RECT 14.700 -0.450 15.300 3.900 ;
        RECT 12.300 -0.450 12.900 3.900 ;
        RECT 9.900 -0.450 10.500 3.900 ;
        RECT 7.500 -0.450 8.100 3.900 ;
        RECT 5.100 -0.450 5.700 3.900 ;
        RECT 2.700 -0.450 3.300 3.900 ;
    END
  END gnd
  PIN Y
    DIRECTION OUTPUT ;
    PORT
      LAYER metal1 ;
        RECT 13.500 0.900 14.100 4.950 ;
        RECT 13.500 7.050 15.300 7.650 ;
        RECT 14.700 4.350 15.300 7.650 ;
        RECT 13.500 4.350 15.300 4.950 ;
        RECT 13.500 7.050 14.100 14.100 ;
    END
  END Y
  PIN vdd
    DIRECTION INOUT ;
    USE POWER ;
    SHAPE ABUTMENT ;
    PORT
      LAYER metal1 ;
        RECT 0.300 8.100 0.900 15.450 ;
        RECT -0.300 14.550 15.900 15.450 ;
        RECT 14.700 8.100 15.300 15.450 ;
        RECT 12.300 8.100 12.900 15.450 ;
        RECT 9.900 8.100 10.500 15.450 ;
        RECT 7.500 8.100 8.100 15.450 ;
        RECT 5.100 8.100 5.700 15.450 ;
        RECT 2.700 8.100 3.300 15.450 ;
    END
  END vdd
  OBS 
      LAYER metal1 ;
        RECT 1.500 0.900 2.100 4.950 ;
        RECT 1.500 4.350 2.850 4.950 ;
        RECT 2.250 5.400 4.200 6.000 ;
        RECT 2.250 4.350 2.850 7.650 ;
        RECT 1.500 7.050 2.850 7.650 ;
        RECT 1.500 7.050 2.100 14.100 ;
        RECT 3.900 0.900 4.500 4.950 ;
        RECT 3.900 4.350 5.550 4.950 ;
        RECT 4.950 5.400 6.750 6.000 ;
        RECT 4.950 4.350 5.550 7.650 ;
        RECT 3.900 7.050 5.550 7.650 ;
        RECT 3.900 7.050 4.500 14.100 ;
        RECT 6.300 0.900 6.900 4.950 ;
        RECT 6.300 4.350 7.950 4.950 ;
        RECT 7.350 5.400 9.300 6.000 ;
        RECT 7.350 4.350 7.950 7.650 ;
        RECT 6.300 7.050 7.950 7.650 ;
        RECT 6.300 7.050 6.900 14.100 ;
        RECT 8.700 0.900 9.300 4.950 ;
        RECT 8.700 4.350 10.500 4.950 ;
        RECT 9.900 5.400 11.250 6.000 ;
        RECT 9.900 4.350 10.500 7.650 ;
        RECT 8.700 7.050 10.500 7.650 ;
        RECT 8.700 7.050 9.300 14.100 ;
        RECT 11.100 0.900 11.700 4.950 ;
        RECT 11.100 4.350 12.450 4.950 ;
        RECT 11.850 5.400 13.800 6.000 ;
        RECT 11.850 4.350 12.450 7.650 ;
        RECT 11.100 7.050 12.450 7.650 ;
        RECT 11.100 7.050 11.700 14.100 ;
  END 
END CLKBUF2

MACRO CLKBUF3
  CLASS  CORE ;
  FOREIGN CLKBUF3 0.000 0.000 ;
  ORIGIN 0.000 0.000 ;
  SIZE 20.400 BY 15.000 ;
  SYMMETRY X Y  ;
  SITE core ;
  PIN A
    DIRECTION INPUT ;
    PORT
      LAYER metal1 ;
        RECT 0.300 4.950 0.900 6.000 ;
        RECT 0.300 5.400 1.650 6.000 ;
    END
  END A
  PIN gnd
    DIRECTION INOUT ;
    USE GROUND ;
    SHAPE ABUTMENT ;
    PORT
      LAYER metal1 ;
        RECT 0.300 -0.450 0.900 3.900 ;
        RECT -0.300 -0.450 20.700 0.450 ;
        RECT 19.500 -0.450 20.100 3.900 ;
        RECT 17.100 -0.450 17.700 3.900 ;
        RECT 14.700 -0.450 15.300 3.900 ;
        RECT 12.300 -0.450 12.900 3.900 ;
        RECT 9.900 -0.450 10.500 3.900 ;
        RECT 7.500 -0.450 8.100 3.900 ;
        RECT 5.100 -0.450 5.700 3.900 ;
        RECT 2.700 -0.450 3.300 3.900 ;
    END
  END gnd
  PIN Y
    DIRECTION OUTPUT ;
    PORT
      LAYER metal1 ;
        RECT 18.300 0.900 18.900 4.950 ;
        RECT 18.300 7.050 20.100 7.650 ;
        RECT 19.500 4.350 20.100 7.650 ;
        RECT 18.300 4.350 20.100 4.950 ;
        RECT 18.300 7.050 18.900 14.100 ;
    END
  END Y
  PIN vdd
    DIRECTION INOUT ;
    USE POWER ;
    SHAPE ABUTMENT ;
    PORT
      LAYER metal1 ;
        RECT 0.300 8.100 0.900 15.450 ;
        RECT -0.300 14.550 20.700 15.450 ;
        RECT 19.500 8.100 20.100 15.450 ;
        RECT 17.100 8.100 17.700 15.450 ;
        RECT 14.700 8.100 15.300 15.450 ;
        RECT 12.300 8.100 12.900 15.450 ;
        RECT 9.900 8.100 10.500 15.450 ;
        RECT 7.500 8.100 8.100 15.450 ;
        RECT 5.100 8.100 5.700 15.450 ;
        RECT 2.700 8.100 3.300 15.450 ;
    END
  END vdd
  OBS 
      LAYER metal1 ;
        RECT 1.500 0.900 2.100 4.950 ;
        RECT 1.500 4.350 2.850 4.950 ;
        RECT 2.250 5.400 4.200 6.000 ;
        RECT 2.250 4.350 2.850 7.650 ;
        RECT 1.500 7.050 2.850 7.650 ;
        RECT 1.500 7.050 2.100 14.100 ;
        RECT 3.900 0.900 4.500 4.950 ;
        RECT 3.900 4.350 5.550 4.950 ;
        RECT 4.950 5.400 6.750 6.000 ;
        RECT 4.950 4.350 5.550 7.650 ;
        RECT 3.900 7.050 5.550 7.650 ;
        RECT 3.900 7.050 4.500 14.100 ;
        RECT 6.300 0.900 6.900 4.950 ;
        RECT 6.300 4.350 7.950 4.950 ;
        RECT 7.350 5.400 9.300 6.000 ;
        RECT 7.350 4.350 7.950 7.650 ;
        RECT 6.300 7.050 7.950 7.650 ;
        RECT 6.300 7.050 6.900 14.100 ;
        RECT 8.700 0.900 9.300 4.950 ;
        RECT 8.700 4.350 10.500 4.950 ;
        RECT 9.900 5.400 11.250 6.000 ;
        RECT 9.900 4.350 10.500 7.650 ;
        RECT 8.700 7.050 10.500 7.650 ;
        RECT 8.700 7.050 9.300 14.100 ;
        RECT 11.100 0.900 11.700 4.950 ;
        RECT 11.100 4.350 12.450 4.950 ;
        RECT 11.850 5.400 13.800 6.000 ;
        RECT 11.850 4.350 12.450 7.650 ;
        RECT 11.100 7.050 12.450 7.650 ;
        RECT 11.100 7.050 11.700 14.100 ;
        RECT 13.500 0.900 14.100 4.950 ;
        RECT 13.500 4.350 15.150 4.950 ;
        RECT 14.550 5.400 16.350 6.000 ;
        RECT 14.550 4.350 15.150 7.650 ;
        RECT 13.500 7.050 15.150 7.650 ;
        RECT 13.500 7.050 14.100 14.100 ;
        RECT 15.900 0.900 16.500 4.950 ;
        RECT 15.900 4.350 17.550 4.950 ;
        RECT 16.950 5.400 18.900 6.000 ;
        RECT 16.950 4.350 17.550 7.650 ;
        RECT 15.900 7.050 17.550 7.650 ;
        RECT 15.900 7.050 16.500 14.100 ;
  END 
END CLKBUF3

END LIBRARY
